VERSION 5.5 ;
NAMESCASESENSITIVE ON ;
BUSBITCHARS "[]" ;
DIVIDERCHAR "/" ;

PROPERTYDEFINITIONS
  LAYER routingPitch REAL ;
END PROPERTYDEFINITIONS

UNITS
  DATABASE MICRONS 1000 ;
END UNITS
MANUFACTURINGGRID 0.01 ;
LAYER POLY1
  TYPE MASTERSLICE ;
END POLY1

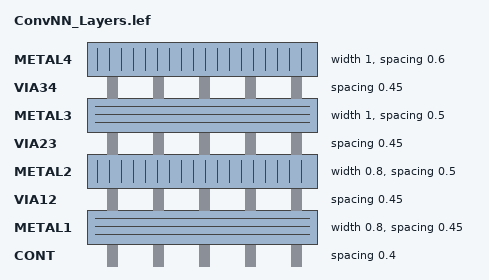
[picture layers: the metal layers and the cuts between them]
LAYER CONT
  TYPE CUT ;
  SPACING 0.4 ;
END CONT

LAYER METAL1
  TYPE ROUTING ;
  DIRECTION HORIZONTAL ;
  PITCH 0 ;
  WIDTH 0.8 ;
  SPACING 0.45 ;
  PROPERTY routingPitch 1.25 ;
END METAL1

LAYER VIA12
  TYPE CUT ;
  SPACING 0.45 ;
END VIA12

LAYER METAL2
  TYPE ROUTING ;
  DIRECTION VERTICAL ;
  PITCH 0 ;
  WIDTH 0.8 ;
  SPACING 0.5 ;
  PROPERTY routingPitch 1.4 ;
END METAL2

LAYER VIA23
  TYPE CUT ;
  SPACING 0.45 ;
END VIA23

LAYER METAL3
  TYPE ROUTING ;
  DIRECTION HORIZONTAL ;
  PITCH 0 ;
  WIDTH 1.0 ;
  SPACING 0.5 ;
  PROPERTY routingPitch 1.25 ;
END METAL3

LAYER VIA34
  TYPE CUT ;
  SPACING 0.45 ;
END VIA34

LAYER METAL4
  TYPE ROUTING ;
  DIRECTION VERTICAL ;
  PITCH 0 ;
  WIDTH 1.0 ;
  SPACING 0.6 ;
  PROPERTY routingPitch 1.4 ;
END METAL4

LAYER OVERLAP
  TYPE OVERLAP ;
END OVERLAP

VIARULE M4_M3 GENERATE
  LAYER METAL3 ;
    ENCLOSURE 0.2 0.2 ;
  LAYER METAL4 ;
    ENCLOSURE 0.15 0.15 ;
  LAYER VIA34 ;
    RECT -0.25 -0.25 0.25 0.25 ;
    SPACING 1 BY 1 ;
END M4_M3

VIARULE M3_M2 GENERATE
  LAYER METAL2 ;
    ENCLOSURE 0.2 0.2 ;
  LAYER METAL3 ;
    ENCLOSURE 0.15 0.15 ;
  LAYER VIA23 ;
    RECT -0.25 -0.25 0.25 0.25 ;
    SPACING 1 BY 1 ;
END M3_M2

VIARULE M2_M1 GENERATE
  LAYER METAL1 ;
    ENCLOSURE 0.2 0.2 ;
  LAYER METAL2 ;
    ENCLOSURE 0.15 0.15 ;
  LAYER VIA12 ;
    RECT -0.25 -0.25 0.25 0.25 ;
    SPACING 1 BY 1 ;
END M2_M1

VIARULE M1_POLY1 GENERATE
  LAYER POLY1 ;
    ENCLOSURE 0.2 0.2 ;
  LAYER METAL1 ;
    ENCLOSURE 0.15 0.15 ;
  LAYER CONT ;
    RECT -0.2 -0.2 0.2 0.2 ;
    SPACING 1 BY 1 ;
END M1_POLY1

VIA M1_POLY1
  LAYER CONT ;
    RECT -0.2 -0.2 0.2 0.2 ;
  LAYER POLY1 ;
    RECT -0.4 -0.4 0.4 0.4 ;
  LAYER METAL1 ;
    RECT -0.35 -0.35 0.35 0.35 ;
END M1_POLY1

VIA M2_M1
  LAYER VIA12 ;
    RECT -0.25 -0.25 0.25 0.25 ;
  LAYER METAL2 ;
    RECT -0.4 -0.4 0.4 0.4 ;
  LAYER METAL1 ;
    RECT -0.45 -0.45 0.45 0.45 ;
END M2_M1

VIA M3_M2
  LAYER VIA23 ;
    RECT -0.25 -0.25 0.25 0.25 ;
  LAYER METAL3 ;
    RECT -0.4 -0.4 0.4 0.4 ;
  LAYER METAL2 ;
    RECT -0.45 -0.45 0.45 0.45 ;
END M3_M2

VIA M4_M3
  LAYER VIA34 ;
    RECT -0.25 -0.25 0.25 0.25 ;
  LAYER METAL4 ;
    RECT -0.4 -0.4 0.4 0.4 ;
  LAYER METAL3 ;
    RECT -0.45 -0.45 0.45 0.45 ;
END M4_M3


MACRO TSMC350nm_VinjDecode2to4_vtile_spacing
END TSMC350nm_VinjDecode2to4_vtile_spacing

MACRO TSMC350nm_VinjDecode2to4_vtile_bridge_spacing
END TSMC350nm_VinjDecode2to4_vtile_bridge_spacing

MACRO TSMC350nm_VinjDecode2to4_vtile_D_bridge
END TSMC350nm_VinjDecode2to4_vtile_D_bridge

MACRO TSMC350nm_VinjDecode2to4_vtile
  PIN Vinj
    DIRECTION INOUT ;
    USE SIGNAL ;
    PORT
      LAYER METAL1 ;
        RECT 7.78 11.04 9.06 11.45 ;
    END
  END Vinj
  PIN OUT<0>
    DIRECTION INOUT ;
    USE SIGNAL ;
    PORT
      LAYER METAL1 ;
        RECT 19.66 18.91 20.11 19.59 ;
    END
  END OUT<0>
  PIN OUT<1>
    DIRECTION INOUT ;
    USE SIGNAL ;
    PORT
      LAYER METAL1 ;
        RECT 19.66 13.41 20.12 14.1 ;
    END
  END OUT<1>
  PIN OUT<2>
    DIRECTION INOUT ;
    USE SIGNAL ;
    PORT
      LAYER METAL1 ;
        RECT 19.66 7.92 20.11 8.59 ;
    END
  END OUT<2>
  PIN OUT<3>
    DIRECTION INOUT ;
    USE SIGNAL ;
    PORT
      LAYER METAL1 ;
        RECT 19.66 2.41 20.11 3.09 ;
    END
  END OUT<3>
  PIN ENABLE
    DIRECTION INOUT ;
    USE SIGNAL ;
    PORT
      LAYER METAL1 ;
        RECT 0.01 3.48 0.71 4.21 ;
    END
  END ENABLE
  PIN GND
    DIRECTION INOUT ;
    USE SIGNAL ;
    PORT
      LAYER METAL1 ;
        RECT 19.52 5.0 20.12 5.99 ;
    END
  END GND
  PIN VINJ
    DIRECTION INOUT ;
    USE SIGNAL ;
    PORT
      LAYER METAL1 ;
        RECT 19.15 21.56 20.05 21.96 ;
    END
  END VINJ
  PIN IN<1>
    DIRECTION INOUT ;
    USE SIGNAL ;
    PORT
      LAYER METAL2 ;
        RECT 6.56 20.89 7.5 22.0 ;
    END
  END IN<1>
  PIN IN<0>
    DIRECTION INOUT ;
    USE SIGNAL ;
    PORT
      LAYER METAL2 ;
        RECT 3.9 20.96 4.5 22.0 ;
    END
  END IN<0>
END TSMC350nm_VinjDecode2to4_vtile

MACRO TSMC350nm_VinjDecode2to4_vtile_C_bridge
END TSMC350nm_VinjDecode2to4_vtile_C_bridge

MACRO TSMC350nm_VinjDecode2to4_vtile_B_bridge
END TSMC350nm_VinjDecode2to4_vtile_B_bridge

MACRO TSMC350nm_VinjDecode2to4_vtile_A_bridge
END TSMC350nm_VinjDecode2to4_vtile_A_bridge

MACRO TSMC350nm_drainSelect_progrundrains
  PIN prog_drain<3>
    DIRECTION INOUT ;
    USE SIGNAL ;
    PORT
      LAYER METAL1 ;
        RECT 30.93 0.93 31.86 1.43 ;
    END
  END prog_drain<3>
  PIN prog_drain<2>
    DIRECTION INOUT ;
    USE SIGNAL ;
    PORT
      LAYER METAL1 ;
        RECT 30.97 9.62 31.86 10.12 ;
    END
  END prog_drain<2>
  PIN prog_drain<1>
    DIRECTION INOUT ;
    USE SIGNAL ;
    PORT
      LAYER METAL1 ;
        RECT 31.0 13.97 31.86 14.47 ;
    END
  END prog_drain<1>
  PIN run_drain<3>
    DIRECTION INOUT ;
    USE SIGNAL ;
    PORT
      LAYER METAL1 ;
        RECT 31.01 2.45 31.86 2.95 ;
    END
  END run_drain<3>
  PIN run_drain<2>
    DIRECTION INOUT ;
    USE SIGNAL ;
    PORT
      LAYER METAL1 ;
        RECT 30.94 5.31 31.86 5.81 ;
    END
  END run_drain<2>
  PIN prog_drain<0>
    DIRECTION INOUT ;
    USE SIGNAL ;
    PORT
      LAYER METAL1 ;
        RECT 31.12 20.75 31.86 21.25 ;
    END
  END prog_drain<0>
  PIN GND
    DIRECTION INOUT ;
    USE SIGNAL ;
    PORT
      LAYER METAL2 ;
        RECT 4.19 21.33 4.99 22.0 ;
    END
  END GND
  PIN VINJ
    DIRECTION INOUT ;
    USE SIGNAL ;
    PORT
      LAYER METAL1 ;
        RECT 1.4 21.5 2.8 22.0 ;
    END
  END VINJ
  PIN run_drain<0>
    DIRECTION INOUT ;
    USE SIGNAL ;
    PORT
      LAYER METAL1 ;
        RECT 31.01 19.56 31.86 20.06 ;
    END
  END run_drain<0>
  PIN run_drain<1>
    DIRECTION INOUT ;
    USE SIGNAL ;
    PORT
      LAYER METAL1 ;
        RECT 31.04 16.75 31.86 17.24 ;
    END
  END run_drain<1>
  PIN SELECT<3>
    DIRECTION INOUT ;
    USE SIGNAL ;
    PORT
      LAYER METAL1 ;
        RECT 0.0 2.54 0.67 2.97 ;
    END
  END SELECT<3>
  PIN SELET<2>
    DIRECTION INOUT ;
    USE SIGNAL ;
    PORT
      LAYER METAL1 ;
        RECT 0.0 8.03 0.67 8.46 ;
    END
  END SELET<2>
  PIN SELECT<1>
    DIRECTION INOUT ;
    USE SIGNAL ;
    PORT
      LAYER METAL1 ;
        RECT 0.0 13.54 0.67 13.97 ;
    END
  END SELECT<1>
  PIN SELECT<0>
    DIRECTION INOUT ;
    USE SIGNAL ;
    PORT
      LAYER METAL1 ;
        RECT 0.0 18.9 0.67 19.6 ;
    END
  END SELECT<0>
  PIN VINJ_b
    DIRECTION INOUT ;
    USE SIGNAL ;
    PORT
      LAYER METAL2 ;
        RECT 21.94 0.0 23.29 0.58 ;
    END
  END VINJ_b
  PIN GND_b
    DIRECTION INOUT ;
    USE SIGNAL ;
    PORT
      LAYER METAL2 ;
        RECT 17.16 0.0 18.16 0.58 ;
    END
  END GND_b
  PIN run_drainrail
    DIRECTION INOUT ;
    USE SIGNAL ;
    PORT
      LAYER METAL2 ;
        RECT 27.01 21.19 27.71 22.0 ;
    END
  END run_drainrail
  PIN prog_drainrail
    DIRECTION INOUT ;
    USE SIGNAL ;
    PORT
      LAYER METAL2 ;
        RECT 7.36 21.34 8.16 22.0 ;
    END
  END prog_drainrail
END TSMC350nm_drainSelect_progrundrains

MACRO TSMC350nm_4TGate_ST_draincutoff
  PIN In<0>
    DIRECTION INOUT ;
    USE SIGNAL ;
    PORT
      LAYER METAL1 ;
        RECT 9.96 17.5 10.6 18.45 ;
    END
  END In<0>
  PIN In<1>
    DIRECTION INOUT ;
    USE SIGNAL ;
    PORT
      LAYER METAL1 ;
        RECT 9.91 14.7 10.6 15.93 ;
    END
  END In<1>
  PIN In<2>
    DIRECTION INOUT ;
    USE SIGNAL ;
    PORT
      LAYER METAL1 ;
        RECT 10.01 6.9 10.6 7.8 ;
    END
  END In<2>
  PIN In<3>
    DIRECTION INOUT ;
    USE SIGNAL ;
    PORT
      LAYER METAL1 ;
        RECT 10.02 3.5 10.6 4.3 ;
    END
  END In<3>
  PIN A<0>
    DIRECTION INOUT ;
    USE SIGNAL ;
    PORT
      LAYER METAL1 ;
        RECT 0.0 19.56 1.4 20.06 ;
    END
  END A<0>
  PIN A<1>
    DIRECTION INOUT ;
    USE SIGNAL ;
    PORT
      LAYER METAL1 ;
        RECT 0.0 16.75 1.4 17.25 ;
    END
  END A<1>
  PIN A<2>
    DIRECTION INOUT ;
    USE SIGNAL ;
    PORT
      LAYER METAL1 ;
        RECT 0.0 5.3 1.4 5.8 ;
    END
  END A<2>
  PIN A<3>
    DIRECTION INOUT ;
    USE SIGNAL ;
    PORT
      LAYER METAL1 ;
        RECT 0.0 2.45 1.4 2.95 ;
    END
  END A<3>
  PIN P<0>
    DIRECTION INOUT ;
    USE SIGNAL ;
    PORT
      LAYER METAL1 ;
        RECT 0.0 20.75 1.4 21.25 ;
    END
  END P<0>
  PIN P<1>
    DIRECTION INOUT ;
    USE SIGNAL ;
    PORT
      LAYER METAL1 ;
        RECT 0.0 13.97 1.4 14.47 ;
    END
  END P<1>
  PIN P<2>
    DIRECTION INOUT ;
    USE SIGNAL ;
    PORT
      LAYER METAL1 ;
        RECT 0.0 9.62 1.4 10.12 ;
    END
  END P<2>
  PIN P<3>
    DIRECTION INOUT ;
    USE SIGNAL ;
    PORT
      LAYER METAL1 ;
        RECT 0.0 0.93 1.4 1.43 ;
    END
  END P<3>
  PIN PR<0>
    DIRECTION INOUT ;
    USE SIGNAL ;
    PORT
      LAYER METAL1 ;
        RECT 10.0 20.3 10.6 21.25 ;
    END
  END PR<0>
  PIN PR<1>
    DIRECTION INOUT ;
    USE SIGNAL ;
    PORT
      LAYER METAL1 ;
        RECT 10.13 11.9 10.6 12.8 ;
    END
  END PR<1>
  PIN PR<2>
    DIRECTION INOUT ;
    USE SIGNAL ;
    PORT
      LAYER METAL1 ;
        RECT 10.0 9.4 10.6 10.3 ;
    END
  END PR<2>
  PIN PR<3>
    DIRECTION INOUT ;
    USE SIGNAL ;
    PORT
      LAYER METAL1 ;
        RECT 10.0 0.7 10.6 1.6 ;
    END
  END PR<3>
  PIN VDD_b
    DIRECTION INOUT ;
    USE SIGNAL ;
    PORT
      LAYER METAL2 ;
        RECT 7.89 0.0 8.79 0.54 ;
    END
  END VDD_b
  PIN RUN
    DIRECTION INOUT ;
    USE SIGNAL ;
    PORT
      LAYER METAL2 ;
        RECT 5.9 21.13 6.5 22.0 ;
    END
  END RUN
  PIN VDD
    DIRECTION INOUT ;
    USE SIGNAL ;
    PORT
      LAYER METAL2 ;
        RECT 7.89 21.3 8.79 22.0 ;
    END
  END VDD
  PIN GND
    DIRECTION INOUT ;
    USE SIGNAL ;
    PORT
      LAYER METAL2 ;
        RECT 3.35 21.3 4.25 22.0 ;
    END
  END GND
  PIN GND_b
    DIRECTION INOUT ;
    USE SIGNAL ;
    PORT
      LAYER METAL2 ;
        RECT 3.35 0.0 4.25 0.73 ;
    END
  END GND_b
  PIN RUN_b
    DIRECTION INOUT ;
    USE SIGNAL ;
    PORT
      LAYER METAL2 ;
        RECT 5.9 0.0 6.5 0.71 ;
    END
  END RUN_b
END TSMC350nm_4TGate_ST_draincutoff

MACRO TSMC350nm_IndirectSwitches
  PIN GND_B<1>
    DIRECTION INOUT ;
    USE SIGNAL ;
    PORT
      LAYER METAL2 ;
        RECT 15.41 0.0 16.01 0.85 ;
    END
  END GND_B<1>
  PIN GND_B<0>
    DIRECTION INOUT ;
    USE SIGNAL ;
    PORT
      LAYER METAL2 ;
        RECT 11.2 0.0 11.8 0.85 ;
    END
  END GND_B<0>
  PIN GND
    DIRECTION INOUT ;
    USE SIGNAL ;
    PORT
      LAYER METAL2 ;
        RECT 11.2 3.21 11.8 3.6 ;
    END
  END GND
  PIN GND_T
    DIRECTION INOUT ;
    USE SIGNAL ;
    PORT
      LAYER METAL2 ;
        RECT 15.4 21.0 16.2 22.0 ;
    END
  END GND_T
  PIN VINJ_T
    DIRECTION INOUT ;
    USE SIGNAL ;
    PORT
      LAYER METAL2 ;
        RECT 6.3 21.04 7.32 22.0 ;
    END
  END VINJ_T
  PIN VDD<1>
    DIRECTION INOUT ;
    USE SIGNAL ;
    PORT
      LAYER METAL2 ;
        RECT 24.5 0.0 25.1 0.75 ;
    END
  END VDD<1>
  PIN VTUN
    DIRECTION INOUT ;
    USE SIGNAL ;
    PORT
      LAYER METAL2 ;
        RECT 13.3 0.0 13.9 0.82 ;
    END
  END VTUN
  PIN VINJ
    DIRECTION INOUT ;
    USE SIGNAL ;
    PORT
      LAYER METAL2 ;
        RECT 4.2 0.0 4.8 1.0 ;
    END
  END VINJ
  PIN VDD<0>
    DIRECTION INOUT ;
    USE SIGNAL ;
    PORT
      LAYER METAL2 ;
        RECT 2.1 0.0 2.7 1.09 ;
    END
  END VDD<0>
  PIN Vg<0>
    DIRECTION INOUT ;
    USE SIGNAL ;
    PORT
      LAYER METAL2 ;
        RECT 8.4 0.005 9.0 0.825 ;
    END
  END Vg<0>
  PIN CTRL_B<0>
    DIRECTION INOUT ;
    USE SIGNAL ;
    PORT
      LAYER METAL2 ;
        RECT 6.3 0.01 6.9 0.76 ;
    END
  END CTRL_B<0>
  PIN CTRL_B<1>
    DIRECTION INOUT ;
    USE SIGNAL ;
    PORT
      LAYER METAL2 ;
        RECT 20.3 0.01 20.9 0.75 ;
    END
  END CTRL_B<1>
  PIN Vg<1>
    DIRECTION INOUT ;
    USE SIGNAL ;
    PORT
      LAYER METAL2 ;
        RECT 18.2 0.0 18.8 0.76 ;
    END
  END Vg<1>
  PIN decode<0>
    DIRECTION INOUT ;
    USE SIGNAL ;
    PORT
      LAYER METAL2 ;
        RECT 3.46 21.16 4.8 22.0 ;
    END
  END decode<0>
  PIN RUN_IN<1>
    DIRECTION INOUT ;
    USE SIGNAL ;
    PORT
      LAYER METAL2 ;
        RECT 17.5 21.01 18.1 22.0 ;
    END
  END RUN_IN<1>
  PIN RUN_IN<0>
    DIRECTION INOUT ;
    USE SIGNAL ;
    PORT
      LAYER METAL2 ;
        RECT 10.5 20.9 11.1 22.0 ;
    END
  END RUN_IN<0>
  PIN VPWR<1>
    DIRECTION INOUT ;
    USE SIGNAL ;
    PORT
      LAYER METAL2 ;
        RECT 21.7 21.08 22.3 22.0 ;
    END
  END VPWR<1>
  PIN decode<1>
    DIRECTION INOUT ;
    USE SIGNAL ;
    PORT
      LAYER METAL2 ;
        RECT 23.8 21.09 25.0 22.0 ;
    END
  END decode<1>
  PIN VPWR<0>
    DIRECTION INOUT ;
    USE SIGNAL ;
    PORT
      LAYER METAL2 ;
        RECT 1.71 21.21 2.43 22.0 ;
    END
  END VPWR<0>
  PIN VTUN_T
    DIRECTION INOUT ;
    USE SIGNAL ;
    PORT
      LAYER METAL2 ;
        RECT 12.6 21.12 13.7 22.0 ;
    END
  END VTUN_T
  PIN vtun_r
    DIRECTION INOUT ;
    USE SIGNAL ;
    PORT
      LAYER METAL1 ;
        RECT 26.17 0.9 27.46 2.17 ;
    END
  END vtun_r
  PIN vgsel_r
    DIRECTION INOUT ;
    USE SIGNAL ;
    PORT
      LAYER METAL1 ;
        RECT 26.52 3.15 27.46 4.45 ;
    END
  END vgsel_r
  PIN prog_r
    DIRECTION INOUT ;
    USE SIGNAL ;
    PORT
      LAYER METAL1 ;
        RECT 26.59 9.15 27.46 10.55 ;
    END
  END prog_r
  PIN run_r
    DIRECTION INOUT ;
    USE SIGNAL ;
    PORT
      LAYER METAL1 ;
        RECT 26.28 6.05 27.46 7.29 ;
    END
  END run_r
  PIN RUN
    DIRECTION INOUT ;
    USE SIGNAL ;
    PORT
      LAYER METAL1 ;
        RECT 0.0 6.05 0.91 7.29 ;
    END
  END RUN
  PIN PROG
    DIRECTION INOUT ;
    USE SIGNAL ;
    PORT
      LAYER METAL1 ;
        RECT 0.0 9.15 0.87 10.55 ;
    END
  END PROG
  PIN Vgsel
    DIRECTION INOUT ;
    USE SIGNAL ;
    PORT
      LAYER METAL1 ;
        RECT 0.0 3.72 0.91 4.45 ;
    END
  END Vgsel
  PIN vtun_l
    DIRECTION INOUT ;
    USE SIGNAL ;
    PORT
      LAYER METAL1 ;
        RECT 0.0 0.9 1.31 1.88 ;
    END
  END vtun_l
END TSMC350nm_IndirectSwitches

MACRO TSMC350nm_VinjDecode2to4_htile
  PIN IN<1>
    DIRECTION INOUT ;
    USE SIGNAL ;
    PORT
      LAYER METAL1 ;
        RECT 0.0 11.85 0.9 12.74 ;
    END
  END IN<1>
  PIN IN<0>
    DIRECTION INOUT ;
    USE SIGNAL ;
    PORT
      LAYER METAL1 ;
        RECT 0.0 10.13 0.87 11.1 ;
    END
  END IN<0>
  PIN VINJ
    DIRECTION INOUT ;
    USE SIGNAL ;
    PORT
      LAYER METAL1 ;
        RECT 0.0 1.99 0.5 2.49 ;
    END
  END VINJ
  PIN GND
    DIRECTION INOUT ;
    USE SIGNAL ;
    PORT
      LAYER METAL1 ;
        RECT 0.0 6.99 0.51 7.49 ;
    END
  END GND
  PIN GND_b<1>
    DIRECTION INOUT ;
    USE SIGNAL ;
    PORT
      LAYER METAL2 ;
        RECT 40.32 0.0 40.92 1.79 ;
    END
  END GND_b<1>
  PIN VINJ_b<1>
    DIRECTION INOUT ;
    USE SIGNAL ;
    PORT
      LAYER METAL2 ;
        RECT 22.1 0.0 22.7 1.44 ;
    END
  END VINJ_b<1>
  PIN GND_b<0>
    DIRECTION INOUT ;
    USE SIGNAL ;
    PORT
      LAYER METAL2 ;
        RECT 18.85 0.0 19.45 1.41 ;
    END
  END GND_b<0>
  PIN VINJ_b<0>
    DIRECTION INOUT ;
    USE SIGNAL ;
    PORT
      LAYER METAL2 ;
        RECT 1.07 0.0 1.67 1.25 ;
    END
  END VINJ_b<0>
  PIN VINJV
    DIRECTION INOUT ;
    USE SIGNAL ;
    PORT
      LAYER METAL2 ;
        RECT 23.7 21.26 24.31 22.0 ;
    END
  END VINJV
  PIN GNDV
    DIRECTION INOUT ;
    USE SIGNAL ;
    PORT
      LAYER METAL2 ;
        RECT 25.84 21.28 26.44 22.0 ;
    END
  END GNDV
  PIN RUN_OUT<3>
    DIRECTION INOUT ;
    USE SIGNAL ;
    PORT
      LAYER METAL2 ;
        RECT 34.39 0.0 35.19 0.86 ;
    END
  END RUN_OUT<3>
  PIN RUN_OUT<2>
    DIRECTION INOUT ;
    USE SIGNAL ;
    PORT
      LAYER METAL2 ;
        RECT 28.77 0.0 29.57 0.86 ;
    END
  END RUN_OUT<2>
  PIN RUN_OUT<1>
    DIRECTION INOUT ;
    USE SIGNAL ;
    PORT
      LAYER METAL2 ;
        RECT 13.5 0.0 14.1 0.86 ;
    END
  END RUN_OUT<1>
  PIN RUN_OUT<0>
    DIRECTION INOUT ;
    USE SIGNAL ;
    PORT
      LAYER METAL2 ;
        RECT 7.34 0.0 8.14 0.86 ;
    END
  END RUN_OUT<0>
  PIN ENABLE
    DIRECTION INOUT ;
    USE SIGNAL ;
    PORT
      LAYER METAL2 ;
        RECT 6.29 21.66 6.89 22.0 ;
    END
  END ENABLE
  PIN OUT<2>
    DIRECTION INOUT ;
    USE SIGNAL ;
    PORT
      LAYER METAL2 ;
        RECT 25.28 0.0 25.87 0.87 ;
    END
  END OUT<2>
  PIN OUT<3>
    DIRECTION INOUT ;
    USE SIGNAL ;
    PORT
      LAYER METAL2 ;
        RECT 37.14 0.0 37.73 0.83 ;
    END
  END OUT<3>
  PIN OUT<0>
    DIRECTION INOUT ;
    USE SIGNAL ;
    PORT
      LAYER METAL2 ;
        RECT 4.27 0.0 4.87 0.86 ;
    END
  END OUT<0>
  PIN OUT<1>
    DIRECTION INOUT ;
    USE SIGNAL ;
    PORT
      LAYER METAL2 ;
        RECT 16.14 0.0 16.72 0.85 ;
    END
  END OUT<1>
  PIN VGRUN<0>
    DIRECTION INOUT ;
    USE SIGNAL ;
    PORT
      LAYER METAL2 ;
        RECT 9.1 21.59 9.7 22.0 ;
    END
  END VGRUN<0>
  PIN VGRUN<1>
    DIRECTION INOUT ;
    USE SIGNAL ;
    PORT
      LAYER METAL2 ;
        RECT 11.2 21.6 11.8 22.0 ;
    END
  END VGRUN<1>
  PIN VGRUN<2>
    DIRECTION INOUT ;
    USE SIGNAL ;
    PORT
      LAYER METAL2 ;
        RECT 28.7 21.71 29.3 22.0 ;
    END
  END VGRUN<2>
  PIN VGRUN<3>
    DIRECTION INOUT ;
    USE SIGNAL ;
    PORT
      LAYER METAL2 ;
        RECT 33.6 21.54 34.2 22.0 ;
    END
  END VGRUN<3>
END TSMC350nm_VinjDecode2to4_htile

MACRO TSMC350nm_VinjDecode2to4_htile_A_bridge
  PIN VGRUN<3>
    DIRECTION INOUT ;
    USE SIGNAL ;
    PORT
      LAYER METAL2 ;
        RECT 34.5 9.46 35.1 10.0 ;
    END
  END VGRUN<3>
  PIN VGRUN<2>
    DIRECTION INOUT ;
    USE SIGNAL ;
    PORT
      LAYER METAL2 ;
        RECT 26.6 9.56 27.2 10.0 ;
    END
  END VGRUN<2>
  PIN VGRUN<1>
    DIRECTION INOUT ;
    USE SIGNAL ;
    PORT
      LAYER METAL2 ;
        RECT 13.5 9.46 14.1 10.0 ;
    END
  END VGRUN<1>
  PIN VGRUN<0>
    DIRECTION INOUT ;
    USE SIGNAL ;
    PORT
      LAYER METAL2 ;
        RECT 5.6 9.52 6.2 10.0 ;
    END
  END VGRUN<0>
END TSMC350nm_VinjDecode2to4_htile_A_bridge

MACRO TSMC350nm_VinjDecode2to4_htile_B_bridge
  PIN VGRUN<0>
    DIRECTION INOUT ;
    USE SIGNAL ;
    PORT
      LAYER METAL2 ;
        RECT 9.1 9.52 9.7 10.0 ;
    END
  END VGRUN<0>
  PIN VGRUN<1>
    DIRECTION INOUT ;
    USE SIGNAL ;
    PORT
      LAYER METAL2 ;
        RECT 11.2 9.52 11.8 10.0 ;
    END
  END VGRUN<1>
  PIN VGRUN<2>
    DIRECTION INOUT ;
    USE SIGNAL ;
    PORT
      LAYER METAL2 ;
        RECT 28.7 9.5 29.3 10.0 ;
    END
  END VGRUN<2>
  PIN VGRUN<3>
    DIRECTION INOUT ;
    USE SIGNAL ;
    PORT
      LAYER METAL2 ;
        RECT 33.6 9.51 34.2 10.0 ;
    END
  END VGRUN<3>
END TSMC350nm_VinjDecode2to4_htile_B_bridge

MACRO TSMC350nm_VinjDecode2to4_htile_C_bridge
  PIN VGRUN<0>
    DIRECTION INOUT ;
    USE SIGNAL ;
    PORT
      LAYER METAL2 ;
        RECT 9.1 9.54 9.7 10.0 ;
    END
  END VGRUN<0>
  PIN VGRUN<1>
    DIRECTION INOUT ;
    USE SIGNAL ;
    PORT
      LAYER METAL2 ;
        RECT 11.2 9.57 11.8 10.0 ;
    END
  END VGRUN<1>
  PIN VGRUN<2>
    DIRECTION INOUT ;
    USE SIGNAL ;
    PORT
      LAYER METAL2 ;
        RECT 28.7 9.59 29.3 10.0 ;
    END
  END VGRUN<2>
  PIN VGRUN<3>
    DIRECTION INOUT ;
    USE SIGNAL ;
    PORT
      LAYER METAL2 ;
        RECT 33.6 9.57 34.2 10.0 ;
    END
  END VGRUN<3>
END TSMC350nm_VinjDecode2to4_htile_C_bridge

MACRO TSMC350nm_VinjDecode2to4_htile_spacing
  PIN VGRUN<0>
    DIRECTION INOUT ;
    USE SIGNAL ;
    PORT
      LAYER METAL2 ;
        RECT 9.1 21.59 9.7 22.0 ;
    END
  END VGRUN<0>
  PIN VGRUN<1>
    DIRECTION INOUT ;
    USE SIGNAL ;
    PORT
      LAYER METAL2 ;
        RECT 11.2 21.52 11.8 22.0 ;
    END
  END VGRUN<1>
  PIN VGRUN<2>
    DIRECTION INOUT ;
    USE SIGNAL ;
    PORT
      LAYER METAL2 ;
        RECT 28.7 21.54 29.3 22.0 ;
    END
  END VGRUN<2>
  PIN VGRUN<3>
    DIRECTION INOUT ;
    USE SIGNAL ;
    PORT
      LAYER METAL2 ;
        RECT 33.6 21.55 34.2 22.0 ;
    END
  END VGRUN<3>
END TSMC350nm_VinjDecode2to4_htile_spacing

MACRO Tgate_swc_fr_Kernel_Vert
  PIN Vimg
    DIRECTION INOUT ;
    USE SIGNAL ;
    PORT
      LAYER METAL1 ;
        RECT 0.0 17.02 0.39 17.72 ;
    END
  END Vimg
  PIN AVDD
    DIRECTION INOUT ;
    USE SIGNAL ;
    PORT
      LAYER METAL1 ;
        RECT 0.0 14.02 0.39 15.02 ;
    END
  END AVDD
  PIN DVDD
    DIRECTION INOUT ;
    USE SIGNAL ;
    PORT
      LAYER METAL1 ;
        RECT 0.0 9.47 0.39 10.47 ;
    END
  END DVDD
  PIN GND
    DIRECTION INOUT ;
    USE SIGNAL ;
    PORT
      LAYER METAL2 ;
        RECT 4.39 21.77 5.19 22.0 ;
    END
  END GND
  PIN Q_bot
    DIRECTION INOUT ;
    USE SIGNAL ;
    PORT
      LAYER METAL2 ;
        RECT 6.57 0.0 7.35 0.35 ;
    END
  END Q_bot
  PIN Vg_R
    DIRECTION INOUT ;
    USE SIGNAL ;
    PORT
      LAYER METAL2 ;
        RECT 1.25 0.0 2.05 0.35 ;
    END
  END Vg_R
  PIN Q
    DIRECTION INOUT ;
    USE SIGNAL ;
    PORT
      LAYER METAL2 ;
        RECT 8.6 21.77 9.2 22.0 ;
    END
  END Q
END Tgate_swc_fr_Kernel_Vert

MACRO AvgPool_TopDig
  PIN intg_nxt_rw
    DIRECTION INOUT ;
    USE SIGNAL ;
    PORT
      LAYER METAL2 ;
        RECT 123.32 0.0 124.72 0.68 ;
    END
  END intg_nxt_rw
  PIN AvgPool_col_ctrl<1>
    DIRECTION INOUT ;
    USE SIGNAL ;
    PORT
      LAYER METAL2 ;
        RECT 98.63 0.0 100.03 0.68 ;
    END
  END AvgPool_col_ctrl<1>
  PIN SR_int_0_Q<2>
    DIRECTION INOUT ;
    USE SIGNAL ;
    PORT
      LAYER METAL2 ;
        RECT 73.89 0.0 75.29 0.68 ;
    END
  END SR_int_0_Q<2>
  PIN SR_int_0_Q<4>
    DIRECTION INOUT ;
    USE SIGNAL ;
    PORT
      LAYER METAL2 ;
        RECT 67.9 0.0 69.3 0.68 ;
    END
  END SR_int_0_Q<4>
  PIN SR_int_0_Q<6>
    DIRECTION INOUT ;
    USE SIGNAL ;
    PORT
      LAYER METAL2 ;
        RECT 61.83 0.0 63.23 0.68 ;
    END
  END SR_int_0_Q<6>
  PIN AvgPool_col_ctrl<0>
    DIRECTION INOUT ;
    USE SIGNAL ;
    PORT
      LAYER METAL2 ;
        RECT 116.11 0.0 117.51 0.68 ;
    END
  END AvgPool_col_ctrl<0>
  PIN SR_int_0_Q<1>
    DIRECTION INOUT ;
    USE SIGNAL ;
    PORT
      LAYER METAL2 ;
        RECT 19.86 0.0 21.26 0.68 ;
    END
  END SR_int_0_Q<1>
  PIN SR_int_0_Q<3>
    DIRECTION INOUT ;
    USE SIGNAL ;
    PORT
      LAYER METAL2 ;
        RECT 25.91 0.0 27.31 0.68 ;
    END
  END SR_int_0_Q<3>
  PIN SR_int_0_Q<0>
    DIRECTION INOUT ;
    USE SIGNAL ;
    PORT
      LAYER METAL2 ;
        RECT 31.89 0.0 33.29 0.68 ;
    END
  END SR_int_0_Q<0>
  PIN SR_int_0_Q<7>
    DIRECTION INOUT ;
    USE SIGNAL ;
    PORT
      LAYER METAL2 ;
        RECT 37.86 0.0 39.26 0.68 ;
    END
  END SR_int_0_Q<7>
  PIN SR_int_0_Q<5>
    DIRECTION INOUT ;
    USE SIGNAL ;
    PORT
      LAYER METAL2 ;
        RECT 49.86 0.0 51.26 0.68 ;
    END
  END SR_int_0_Q<5>
  PIN int_rst<0>
    DIRECTION INOUT ;
    USE SIGNAL ;
    PORT
      LAYER METAL1 ;
        RECT 132.77 29.44 133.45 30.84 ;
    END
  END int_rst<0>
  PIN Global_rst_b
    DIRECTION INOUT ;
    USE SIGNAL ;
    PORT
      LAYER METAL1 ;
        RECT 132.77 47.29 133.45 48.69 ;
    END
  END Global_rst_b
  PIN int_rst<1>
    DIRECTION INOUT ;
    USE SIGNAL ;
    PORT
      LAYER METAL1 ;
        RECT 132.77 56.93 133.45 58.33 ;
    END
  END int_rst<1>
  PIN Relu_en_b<0>
    DIRECTION INOUT ;
    USE SIGNAL ;
    PORT
      LAYER METAL1 ;
        RECT 132.77 40.37 133.45 41.77 ;
    END
  END Relu_en_b<0>
  PIN Relu_en_b<1>
    DIRECTION INOUT ;
    USE SIGNAL ;
    PORT
      LAYER METAL1 ;
        RECT 132.77 22.47 133.45 23.87 ;
    END
  END Relu_en_b<1>
  PIN GND
    DIRECTION INOUT ;
    USE SIGNAL ;
    PORT
      LAYER METAL1 ;
        RECT 132.77 6.16 133.45 7.99 ;
    END
  END GND
  PIN DVDD
    DIRECTION INOUT ;
    USE SIGNAL ;
    PORT
      LAYER METAL1 ;
        RECT 132.77 16.35 133.45 18.18 ;
    END
  END DVDD
  PIN SR_int_CLK
    DIRECTION INOUT ;
    USE SIGNAL ;
    PORT
      LAYER METAL1 ;
        RECT 0.0 26.72 0.68 28.12 ;
    END
  END SR_int_CLK
  PIN SR_int_CLKB
    DIRECTION INOUT ;
    USE SIGNAL ;
    PORT
      LAYER METAL1 ;
        RECT 0.0 31.64 0.68 33.04 ;
    END
  END SR_int_CLKB
  PIN SR_int_RST_B
    DIRECTION INOUT ;
    USE SIGNAL ;
    PORT
      LAYER METAL1 ;
        RECT 0.0 37.24 0.68 38.64 ;
    END
  END SR_int_RST_B
  PIN Final_rw
    DIRECTION INOUT ;
    USE SIGNAL ;
    PORT
      LAYER METAL1 ;
        RECT 0.0 40.94 0.68 42.34 ;
    END
  END Final_rw
  PIN SR_k_row_CLKB
    DIRECTION INOUT ;
    USE SIGNAL ;
    PORT
      LAYER METAL1 ;
        RECT 0.0 48.47 0.68 49.87 ;
    END
  END SR_k_row_CLKB
  PIN SR_k_row_RST_B
    DIRECTION INOUT ;
    USE SIGNAL ;
    PORT
      LAYER METAL1 ;
        RECT 0.0 51.32 0.68 52.72 ;
    END
  END SR_k_row_RST_B
  PIN SR_k_row_CLK
    DIRECTION INOUT ;
    USE SIGNAL ;
    PORT
      LAYER METAL1 ;
        RECT 0.0 55.55 0.68 56.95 ;
    END
  END SR_k_row_CLK
END AvgPool_TopDig

MACRO TSMC350nm_4TGate_ST_BMatrix
  PIN In<0>
    DIRECTION INOUT ;
    USE SIGNAL ;
    PORT
      LAYER METAL1 ;
        RECT 0.0 17.5 0.27 18.0 ;
    END
  END In<0>
  PIN In<1>
    DIRECTION INOUT ;
    USE SIGNAL ;
    PORT
      LAYER METAL1 ;
        RECT 0.0 14.7 0.38 15.2 ;
    END
  END In<1>
  PIN In<2>
    DIRECTION INOUT ;
    USE SIGNAL ;
    PORT
      LAYER METAL1 ;
        RECT 0.0 7.0 0.36 7.5 ;
    END
  END In<2>
  PIN In<3>
    DIRECTION INOUT ;
    USE SIGNAL ;
    PORT
      LAYER METAL1 ;
        RECT 0.0 3.5 0.3 4.0 ;
    END
  END In<3>
  PIN A<0>
    DIRECTION INOUT ;
    USE SIGNAL ;
    PORT
      LAYER METAL1 ;
        RECT 10.6 17.6 12.0 18.9 ;
    END
  END A<0>
  PIN A<1>
    DIRECTION INOUT ;
    USE SIGNAL ;
    PORT
      LAYER METAL1 ;
        RECT 10.6 14.9 12.0 16.2 ;
    END
  END A<1>
  PIN A<2>
    DIRECTION INOUT ;
    USE SIGNAL ;
    PORT
      LAYER METAL1 ;
        RECT 10.6 6.8 12.0 8.1 ;
    END
  END A<2>
  PIN A<3>
    DIRECTION INOUT ;
    USE SIGNAL ;
    PORT
      LAYER METAL1 ;
        RECT 10.6 4.1 12.0 5.4 ;
    END
  END A<3>
  PIN P<0>
    DIRECTION INOUT ;
    USE SIGNAL ;
    PORT
      LAYER METAL1 ;
        RECT 10.6 20.3 12.0 21.6 ;
    END
  END P<0>
  PIN P<1>
    DIRECTION INOUT ;
    USE SIGNAL ;
    PORT
      LAYER METAL1 ;
        RECT 10.6 12.2 12.0 13.5 ;
    END
  END P<1>
  PIN P<2>
    DIRECTION INOUT ;
    USE SIGNAL ;
    PORT
      LAYER METAL1 ;
        RECT 10.6 9.5 12.0 10.8 ;
    END
  END P<2>
  PIN P<3>
    DIRECTION INOUT ;
    USE SIGNAL ;
    PORT
      LAYER METAL1 ;
        RECT 10.6 1.4 12.0 2.7 ;
    END
  END P<3>
  PIN GND_b
    DIRECTION INOUT ;
    USE SIGNAL ;
    PORT
      LAYER METAL2 ;
        RECT 6.35 0.0 7.25 0.88 ;
    END
  END GND_b
  PIN Prog_b
    DIRECTION INOUT ;
    USE SIGNAL ;
    PORT
      LAYER METAL2 ;
        RECT 4.1 0.0 4.7 0.78 ;
    END
  END Prog_b
  PIN VDD_b
    DIRECTION INOUT ;
    USE SIGNAL ;
    PORT
      LAYER METAL2 ;
        RECT 1.81 0.0 2.71 0.71 ;
    END
  END VDD_b
  PIN Prog
    DIRECTION INOUT ;
    USE SIGNAL ;
    PORT
      LAYER METAL2 ;
        RECT 4.1 21.3 4.7 22.0 ;
    END
  END Prog
  PIN VDD
    DIRECTION INOUT ;
    USE SIGNAL ;
    PORT
      LAYER METAL2 ;
        RECT 1.81 21.3 2.71 22.0 ;
    END
  END VDD
  PIN GND
    DIRECTION INOUT ;
    USE SIGNAL ;
    PORT
      LAYER METAL2 ;
        RECT 6.35 21.3 7.25 22.0 ;
    END
  END GND
END TSMC350nm_4TGate_ST_BMatrix

MACRO TSMC350nm_VinjDecode2to4_htile_D_bridge
  PIN VGRUN<0>
    DIRECTION INOUT ;
    USE SIGNAL ;
    PORT
      LAYER METAL2 ;
        RECT 9.1 9.58 9.7 10.0 ;
    END
  END VGRUN<0>
  PIN VGRUN<1>
    DIRECTION INOUT ;
    USE SIGNAL ;
    PORT
      LAYER METAL2 ;
        RECT 11.2 9.55 11.8 10.0 ;
    END
  END VGRUN<1>
  PIN VGRUN<2>
    DIRECTION INOUT ;
    USE SIGNAL ;
    PORT
      LAYER METAL2 ;
        RECT 28.7 9.58 29.3 10.0 ;
    END
  END VGRUN<2>
  PIN VGRUN<3>
    DIRECTION INOUT ;
    USE SIGNAL ;
    PORT
      LAYER METAL2 ;
        RECT 33.6 9.57 34.2 10.0 ;
    END
  END VGRUN<3>
END TSMC350nm_VinjDecode2to4_htile_D_bridge

MACRO TSMC350nm_VinjDecode2to4_htile_bridge_spacing
  PIN VGRUN<0>
    DIRECTION INOUT ;
    USE SIGNAL ;
    PORT
      LAYER METAL2 ;
        RECT 9.1 9.52 9.7 9.99 ;
    END
  END VGRUN<0>
  PIN VGRUN<1>
    DIRECTION INOUT ;
    USE SIGNAL ;
    PORT
      LAYER METAL2 ;
        RECT 11.2 9.51 11.8 9.99 ;
    END
  END VGRUN<1>
  PIN VGRUN<2>
    DIRECTION INOUT ;
    USE SIGNAL ;
    PORT
      LAYER METAL2 ;
        RECT 28.7 9.41 29.3 9.99 ;
    END
  END VGRUN<2>
  PIN VGRUN<3>
    DIRECTION INOUT ;
    USE SIGNAL ;
    PORT
      LAYER METAL2 ;
        RECT 33.6 9.47 34.2 9.99 ;
    END
  END VGRUN<3>
END TSMC350nm_VinjDecode2to4_htile_bridge_spacing

MACRO Conv_TopDig
  PIN SR_int_0_Q<0>
    DIRECTION INOUT ;
    USE SIGNAL ;
    PORT
      LAYER METAL2 ;
        RECT 34.15 0.0 35.55 0.68 ;
    END
  END SR_int_0_Q<0>
  PIN SR_int_CLK
    DIRECTION INOUT ;
    USE SIGNAL ;
    PORT
      LAYER METAL2 ;
        RECT 20.27 0.0 21.67 0.68 ;
    END
  END SR_int_CLK
  PIN SR_int_CLKB
    DIRECTION INOUT ;
    USE SIGNAL ;
    PORT
      LAYER METAL2 ;
        RECT 23.72 0.0 25.12 0.68 ;
    END
  END SR_int_CLKB
  PIN SR_int_RST_B
    DIRECTION INOUT ;
    USE SIGNAL ;
    PORT
      LAYER METAL2 ;
        RECT 1.66 0.0 3.06 0.68 ;
    END
  END SR_int_RST_B
  PIN Final_rw
    DIRECTION INOUT ;
    USE SIGNAL ;
    PORT
      LAYER METAL2 ;
        RECT 15.0 43.32 16.4 44.0 ;
    END
  END Final_rw
  PIN SR_int_0_Q2
    DIRECTION INOUT ;
    USE SIGNAL ;
    PORT
      LAYER METAL2 ;
        RECT 68.24 0.0 69.64 0.68 ;
    END
  END SR_int_0_Q2
  PIN sample_nxt_rw
    DIRECTION INOUT ;
    USE SIGNAL ;
    PORT
      LAYER METAL2 ;
        RECT 57.17 43.32 58.57 44.0 ;
    END
  END sample_nxt_rw
  PIN SR_int_0_Q<1>
    DIRECTION INOUT ;
    USE SIGNAL ;
    PORT
      LAYER METAL2 ;
        RECT 52.22 0.0 53.62 0.68 ;
    END
  END SR_int_0_Q<1>
  PIN Readout_flag_gt
    DIRECTION INOUT ;
    USE SIGNAL ;
    PORT
      LAYER METAL2 ;
        RECT 75.75 0.0 77.15 0.68 ;
    END
  END Readout_flag_gt
  PIN Global_rst_b
    DIRECTION INOUT ;
    USE SIGNAL ;
    PORT
      LAYER METAL1 ;
        RECT 115.68 25.31 116.36 26.71 ;
    END
  END Global_rst_b
  PIN int_rst<1>
    DIRECTION INOUT ;
    USE SIGNAL ;
    PORT
      LAYER METAL1 ;
        RECT 115.68 34.95 116.36 36.35 ;
    END
  END int_rst<1>
  PIN DVDD
    DIRECTION INOUT ;
    USE SIGNAL ;
    PORT
      LAYER METAL1 ;
        RECT 115.68 15.9 116.36 17.91 ;
    END
  END DVDD
  PIN GND
    DIRECTION INOUT ;
    USE SIGNAL ;
    PORT
      LAYER METAL1 ;
        RECT 115.68 5.68 116.36 7.69 ;
    END
  END GND
  PIN int_rst<0>
    DIRECTION INOUT ;
    USE SIGNAL ;
    PORT
      LAYER METAL1 ;
        RECT 115.68 1.55 116.36 2.95 ;
    END
  END int_rst<0>
END Conv_TopDig

MACRO Integration_fr_AvgPool_core
  PIN GND
    DIRECTION INOUT ;
    USE SIGNAL ;
    PORT
      LAYER METAL1 ;
        RECT 71.84 21.51 73.23 22.0 ;
    END
  END GND
  PIN Q
    DIRECTION INOUT ;
    USE SIGNAL ;
    PORT
      LAYER METAL3 ;
        RECT 1.45 6.24 3.25 7.04 ;
    END
  END Q
  PIN Vd_prog
    DIRECTION INOUT ;
    USE SIGNAL ;
    PORT
      LAYER METAL2 ;
        RECT 0.0 20.43 0.37 21.23 ;
    END
  END Vd_prog
  PIN int_rst
    DIRECTION INOUT ;
    USE SIGNAL ;
    PORT
      LAYER METAL2 ;
        RECT 0.0 13.45 0.37 14.25 ;
    END
  END int_rst
  PIN Vint
    DIRECTION INOUT ;
    USE SIGNAL ;
    PORT
      LAYER METAL2 ;
        RECT 0.0 14.95 0.37 15.75 ;
    END
  END Vint
  PIN DVDD
    DIRECTION INOUT ;
    USE SIGNAL ;
    PORT
      LAYER METAL2 ;
        RECT 0.0 11.95 0.37 12.75 ;
    END
  END DVDD
  PIN Din
    DIRECTION INOUT ;
    USE SIGNAL ;
    PORT
      LAYER METAL3 ;
        RECT 1.45 2.15 3.25 2.95 ;
    END
  END Din
  PIN RST_B
    DIRECTION INOUT ;
    USE SIGNAL ;
    PORT
      LAYER METAL1 ;
        RECT 14.55 21.51 15.35 22.0 ;
    END
  END RST_B
  PIN CLK
    DIRECTION INOUT ;
    USE SIGNAL ;
    PORT
      LAYER METAL1 ;
        RECT 13.14 21.51 14.1 22.0 ;
    END
  END CLK
  PIN Vimg_CLK
    DIRECTION INOUT ;
    USE SIGNAL ;
    PORT
      LAYER METAL1 ;
        RECT 27.28 21.51 28.28 22.0 ;
    END
  END Vimg_CLK
  PIN CLKB
    DIRECTION INOUT ;
    USE SIGNAL ;
    PORT
      LAYER METAL1 ;
        RECT 11.61 21.51 12.61 22.0 ;
    END
  END CLKB
  PIN nxt_row<1>
    DIRECTION INOUT ;
    USE SIGNAL ;
    PORT
      LAYER METAL1 ;
        RECT 288.77 21.52 289.77 22.0 ;
    END
  END nxt_row<1>
  PIN AVDD_by_2<1>
    DIRECTION INOUT ;
    USE SIGNAL ;
    PORT
      LAYER METAL1 ;
        RECT 196.16 21.52 197.16 22.0 ;
    END
  END AVDD_by_2<1>
  PIN prog<1>
    DIRECTION INOUT ;
    USE SIGNAL ;
    PORT
      LAYER METAL1 ;
        RECT 193.74 21.52 194.74 22.0 ;
    END
  END prog<1>
  PIN run<1>
    DIRECTION INOUT ;
    USE SIGNAL ;
    PORT
      LAYER METAL1 ;
        RECT 191.34 21.52 192.34 22.0 ;
    END
  END run<1>
  PIN Vg<1>
    DIRECTION INOUT ;
    USE SIGNAL ;
    PORT
      LAYER METAL1 ;
        RECT 188.94 21.52 189.94 22.0 ;
    END
  END Vg<1>
  PIN Vsel_b<1>
    DIRECTION INOUT ;
    USE SIGNAL ;
    PORT
      LAYER METAL1 ;
        RECT 186.44 21.51 187.44 22.0 ;
    END
  END Vsel_b<1>
  PIN VINJ<1>
    DIRECTION INOUT ;
    USE SIGNAL ;
    PORT
      LAYER METAL1 ;
        RECT 176.33 21.51 177.33 22.0 ;
    END
  END VINJ<1>
  PIN VTUN
    DIRECTION INOUT ;
    USE SIGNAL ;
    PORT
      LAYER METAL1 ;
        RECT 167.37 21.51 168.37 22.0 ;
    END
  END VTUN
  PIN VINJ<0>
    DIRECTION INOUT ;
    USE SIGNAL ;
    PORT
      LAYER METAL1 ;
        RECT 158.43 21.51 159.43 22.0 ;
    END
  END VINJ<0>
  PIN Vsel_b<0>
    DIRECTION INOUT ;
    USE SIGNAL ;
    PORT
      LAYER METAL1 ;
        RECT 148.32 21.51 149.32 22.0 ;
    END
  END Vsel_b<0>
  PIN Vg<0>
    DIRECTION INOUT ;
    USE SIGNAL ;
    PORT
      LAYER METAL1 ;
        RECT 145.82 21.51 146.82 22.0 ;
    END
  END Vg<0>
  PIN run<0>
    DIRECTION INOUT ;
    USE SIGNAL ;
    PORT
      LAYER METAL1 ;
        RECT 143.42 21.51 144.42 22.0 ;
    END
  END run<0>
  PIN prog<0>
    DIRECTION INOUT ;
    USE SIGNAL ;
    PORT
      LAYER METAL1 ;
        RECT 141.02 21.51 142.02 22.0 ;
    END
  END prog<0>
  PIN AVDD_by_2<0>
    DIRECTION INOUT ;
    USE SIGNAL ;
    PORT
      LAYER METAL1 ;
        RECT 138.6 21.51 139.6 22.0 ;
    END
  END AVDD_by_2<0>
  PIN nxt_row<0>
    DIRECTION INOUT ;
    USE SIGNAL ;
    PORT
      LAYER METAL1 ;
        RECT 45.99 21.51 46.99 22.0 ;
    END
  END nxt_row<0>
END Integration_fr_AvgPool_core

MACRO I_Subtractor_Conv_top
  PIN I_m
    DIRECTION INOUT ;
    USE SIGNAL ;
    PORT
      LAYER METAL2 ;
        RECT 0.0 12.7 0.37 13.7 ;
    END
  END I_m
  PIN Vint
    DIRECTION INOUT ;
    USE SIGNAL ;
    PORT
      LAYER METAL2 ;
        RECT 0.0 16.27 0.37 17.27 ;
    END
  END Vint
  PIN Read_flag_out
    DIRECTION INOUT ;
    USE SIGNAL ;
    PORT
      LAYER METAL2 ;
        RECT 31.12 18.1 31.49 18.9 ;
    END
  END Read_flag_out
  PIN GND
    DIRECTION INOUT ;
    USE SIGNAL ;
    PORT
      LAYER METAL1 ;
        RECT 10.68 20.78 18.71 21.76 ;
    END
  END GND
  PIN Readout_flag_in
    DIRECTION INOUT ;
    USE SIGNAL ;
    PORT
      LAYER METAL1 ;
        RECT 29.72 21.45 30.72 22.0 ;
    END
  END Readout_flag_in
END I_Subtractor_Conv_top

MACRO I_Subtractor_AvgPool_top
  PIN I_m
    DIRECTION INOUT ;
    USE SIGNAL ;
    PORT
      LAYER METAL2 ;
        RECT 0.0 12.7 0.37 13.7 ;
    END
  END I_m
  PIN Vd_prog_krnl
    DIRECTION INOUT ;
    USE SIGNAL ;
    PORT
      LAYER METAL2 ;
        RECT 0.0 18.88 0.37 19.88 ;
    END
  END Vd_prog_krnl
  PIN Vd_prog_avg_pool
    DIRECTION INOUT ;
    USE SIGNAL ;
    PORT
      LAYER METAL2 ;
        RECT 38.54 20.43 38.91 21.23 ;
    END
  END Vd_prog_avg_pool
  PIN Vint
    DIRECTION INOUT ;
    USE SIGNAL ;
    PORT
      LAYER METAL2 ;
        RECT 0.0 16.27 0.37 17.27 ;
    END
  END Vint
  PIN GND
    DIRECTION INOUT ;
    USE SIGNAL ;
    PORT
      LAYER METAL1 ;
        RECT 12.02 21.54 17.24 22.0 ;
    END
  END GND
  PIN run_hv
    DIRECTION INOUT ;
    USE SIGNAL ;
    PORT
      LAYER METAL1 ;
        RECT 36.65 21.54 37.65 22.0 ;
    END
  END run_hv
  PIN VINJ
    DIRECTION INOUT ;
    USE SIGNAL ;
    PORT
      LAYER METAL1 ;
        RECT 31.8 21.54 32.8 22.0 ;
    END
  END VINJ
  PIN prog_hv
    DIRECTION INOUT ;
    USE SIGNAL ;
    PORT
      LAYER METAL1 ;
        RECT 29.8 21.54 30.8 22.0 ;
    END
  END prog_hv
END I_Subtractor_AvgPool_top

MACRO Routes_GateDecodeSwc
  PIN AVDD
    DIRECTION INOUT ;
    USE SIGNAL ;
    PORT
      LAYER METAL1 ;
        RECT 0.0 5.4 0.37 5.9 ;
    END
  END AVDD
END Routes_GateDecodeSwc

MACRO Flatten_Conv_nxtrw_b
  PIN GND
    DIRECTION INOUT ;
    USE SIGNAL ;
    PORT
      LAYER METAL2 ;
        RECT 106.72 3.51 107.18 4.91 ;
    END
  END GND
  PIN nxt_rw
    DIRECTION INOUT ;
    USE SIGNAL ;
    PORT
      LAYER METAL1 ;
        RECT 1.76 21.57 2.76 22.0 ;
    END
  END nxt_rw
  PIN Vb
    DIRECTION INOUT ;
    USE SIGNAL ;
    PORT
      LAYER METAL1 ;
        RECT 34.96 21.57 35.96 22.0 ;
    END
  END Vb
  PIN DVDD
    DIRECTION INOUT ;
    USE SIGNAL ;
    PORT
      LAYER METAL1 ;
        RECT 37.46 21.57 38.46 22.0 ;
    END
  END DVDD
  PIN Vinp
    DIRECTION INOUT ;
    USE SIGNAL ;
    PORT
      LAYER METAL2 ;
        RECT 106.72 0.99 107.18 2.39 ;
    END
  END Vinp
  PIN Q_1_out
    DIRECTION INOUT ;
    USE SIGNAL ;
    PORT
      LAYER METAL2 ;
        RECT 0.0 5.66 0.46 6.66 ;
    END
  END Q_1_out
  PIN Q_1_in
    DIRECTION INOUT ;
    USE SIGNAL ;
    PORT
      LAYER METAL2 ;
        RECT 106.46 5.66 107.18 7.89 ;
    END
  END Q_1_in
  PIN sample
    DIRECTION INOUT ;
    USE SIGNAL ;
    PORT
      LAYER METAL3 ;
        RECT 7.18 12.01 8.98 12.81 ;
    END
  END sample
  PIN Sub_img_out
    DIRECTION INOUT ;
    USE SIGNAL ;
    PORT
      LAYER METAL3 ;
        RECT 97.08 19.0 99.02 20.0 ;
    END
  END Sub_img_out
END Flatten_Conv_nxtrw_b

MACRO TSMC350nm_4x2_Indirect
  PIN Vg<1>
    DIRECTION INOUT ;
    USE SIGNAL ;
    PORT
      LAYER METAL2 ;
        RECT 18.2 21.06 18.8 22.0 ;
    END
  END Vg<1>
  PIN Vsel<1>
    DIRECTION INOUT ;
    USE SIGNAL ;
    PORT
      LAYER METAL2 ;
        RECT 20.3 21.08 20.9 22.0 ;
    END
  END Vsel<1>
  PIN VINJ<1>
    DIRECTION INOUT ;
    USE SIGNAL ;
    PORT
      LAYER METAL2 ;
        RECT 22.4 21.05 23.0 22.0 ;
    END
  END VINJ<1>
  PIN Vsel<0>
    DIRECTION INOUT ;
    USE SIGNAL ;
    PORT
      LAYER METAL2 ;
        RECT 6.3 21.2 6.9 22.0 ;
    END
  END Vsel<0>
  PIN Vs<0>
    DIRECTION INOUT ;
    USE SIGNAL ;
    PORT
      LAYER METAL2 ;
        RECT 2.1 21.21 2.7 22.0 ;
    END
  END Vs<0>
  PIN Vs<1>
    DIRECTION INOUT ;
    USE SIGNAL ;
    PORT
      LAYER METAL2 ;
        RECT 24.5 21.06 25.1 22.0 ;
    END
  END Vs<1>
  PIN VTUN
    DIRECTION INOUT ;
    USE SIGNAL ;
    PORT
      LAYER METAL2 ;
        RECT 13.3 21.09 13.9 22.0 ;
    END
  END VTUN
  PIN VINJ<0>
    DIRECTION INOUT ;
    USE SIGNAL ;
    PORT
      LAYER METAL2 ;
        RECT 4.2 21.18 4.8 22.0 ;
    END
  END VINJ<0>
  PIN GND<0>
    DIRECTION INOUT ;
    USE SIGNAL ;
    PORT
      LAYER METAL2 ;
        RECT 11.2 21.07 11.8 22.0 ;
    END
  END GND<0>
  PIN Vg<0>
    DIRECTION INOUT ;
    USE SIGNAL ;
    PORT
      LAYER METAL2 ;
        RECT 8.4 21.03 9.0 22.0 ;
    END
  END Vg<0>
  PIN GND<1>
    DIRECTION INOUT ;
    USE SIGNAL ;
    PORT
      LAYER METAL2 ;
        RECT 15.41 21.06 16.01 22.0 ;
    END
  END GND<1>
  PIN Vs_b<0>
    DIRECTION INOUT ;
    USE SIGNAL ;
    PORT
      LAYER METAL2 ;
        RECT 1.42 0.0 2.7 0.6 ;
    END
  END Vs_b<0>
  PIN VINJ_b<0>
    DIRECTION INOUT ;
    USE SIGNAL ;
    PORT
      LAYER METAL2 ;
        RECT 4.2 0.0 4.8 0.76 ;
    END
  END VINJ_b<0>
  PIN Vsel_b<0>
    DIRECTION INOUT ;
    USE SIGNAL ;
    PORT
      LAYER METAL2 ;
        RECT 6.3 0.0 6.9 0.78 ;
    END
  END Vsel_b<0>
  PIN Vg_b<0>
    DIRECTION INOUT ;
    USE SIGNAL ;
    PORT
      LAYER METAL2 ;
        RECT 8.4 0.0 9.0 0.77 ;
    END
  END Vg_b<0>
  PIN GND_b<0>
    DIRECTION INOUT ;
    USE SIGNAL ;
    PORT
      LAYER METAL2 ;
        RECT 11.2 0.0 11.8 0.76 ;
    END
  END GND_b<0>
  PIN VTUN_b
    DIRECTION INOUT ;
    USE SIGNAL ;
    PORT
      LAYER METAL2 ;
        RECT 13.3 0.0 13.9 0.76 ;
    END
  END VTUN_b
  PIN GND_b<1>
    DIRECTION INOUT ;
    USE SIGNAL ;
    PORT
      LAYER METAL2 ;
        RECT 15.41 0.0 16.01 0.83 ;
    END
  END GND_b<1>
  PIN Vg_b<1>
    DIRECTION INOUT ;
    USE SIGNAL ;
    PORT
      LAYER METAL2 ;
        RECT 18.2 0.0 18.8 0.76 ;
    END
  END Vg_b<1>
  PIN Vsel_b<1>
    DIRECTION INOUT ;
    USE SIGNAL ;
    PORT
      LAYER METAL2 ;
        RECT 20.3 0.0 20.9 0.75 ;
    END
  END Vsel_b<1>
  PIN VINJ_b<1>
    DIRECTION INOUT ;
    USE SIGNAL ;
    PORT
      LAYER METAL2 ;
        RECT 22.4 0.0 23.0 0.77 ;
    END
  END VINJ_b<1>
  PIN Vs_b<1>
    DIRECTION INOUT ;
    USE SIGNAL ;
    PORT
      LAYER METAL2 ;
        RECT 24.5 0.0 25.75 0.61 ;
    END
  END Vs_b<1>
  PIN Vd_Pl<3>
    DIRECTION INOUT ;
    USE SIGNAL ;
    PORT
      LAYER METAL1 ;
        RECT 0.0 0.7 1.47 1.2 ;
    END
  END Vd_Pl<3>
  PIN Vd_Rl<3>
    DIRECTION INOUT ;
    USE SIGNAL ;
    PORT
      LAYER METAL1 ;
        RECT 0.0 3.5 1.45 4.0 ;
    END
  END Vd_Rl<3>
  PIN Vd_Rl<2>
    DIRECTION INOUT ;
    USE SIGNAL ;
    PORT
      LAYER METAL1 ;
        RECT 0.0 7.0 1.4 7.5 ;
    END
  END Vd_Rl<2>
  PIN Vd_Pl<2>
    DIRECTION INOUT ;
    USE SIGNAL ;
    PORT
      LAYER METAL1 ;
        RECT 0.0 9.8 1.41 10.3 ;
    END
  END Vd_Pl<2>
  PIN Vd_Pl<1>
    DIRECTION INOUT ;
    USE SIGNAL ;
    PORT
      LAYER METAL1 ;
        RECT 0.0 11.89 1.43 12.4 ;
    END
  END Vd_Pl<1>
  PIN Vd_Rl<1>
    DIRECTION INOUT ;
    USE SIGNAL ;
    PORT
      LAYER METAL1 ;
        RECT 0.0 14.7 1.46 15.2 ;
    END
  END Vd_Rl<1>
  PIN Vd_Rl<0>
    DIRECTION INOUT ;
    USE SIGNAL ;
    PORT
      LAYER METAL1 ;
        RECT 0.0 17.5 1.43 18.0 ;
    END
  END Vd_Rl<0>
  PIN Vd_Pl<0>
    DIRECTION INOUT ;
    USE SIGNAL ;
    PORT
      LAYER METAL1 ;
        RECT 0.0 20.3 1.4 20.9 ;
    END
  END Vd_Pl<0>
  PIN Vd_P<0>
    DIRECTION INOUT ;
    USE SIGNAL ;
    PORT
      LAYER METAL1 ;
        RECT 26.63 20.3 27.46 20.8 ;
    END
  END Vd_P<0>
  PIN Vd_R<1>
    DIRECTION INOUT ;
    USE SIGNAL ;
    PORT
      LAYER METAL1 ;
        RECT 26.56 14.7 27.44 15.2 ;
    END
  END Vd_R<1>
  PIN Vd_R<3>
    DIRECTION INOUT ;
    USE SIGNAL ;
    PORT
      LAYER METAL1 ;
        RECT 26.5 3.5 27.46 4.0 ;
    END
  END Vd_R<3>
  PIN Vd_P<3>
    DIRECTION INOUT ;
    USE SIGNAL ;
    PORT
      LAYER METAL1 ;
        RECT 26.55 0.7 27.46 1.2 ;
    END
  END Vd_P<3>
  PIN Vd_P<1>
    DIRECTION INOUT ;
    USE SIGNAL ;
    PORT
      LAYER METAL1 ;
        RECT 26.38 11.9 27.46 12.4 ;
    END
  END Vd_P<1>
  PIN Vd_P<2>
    DIRECTION INOUT ;
    USE SIGNAL ;
    PORT
      LAYER METAL1 ;
        RECT 26.51 9.8 27.46 10.3 ;
    END
  END Vd_P<2>
  PIN Vd_R<0>
    DIRECTION INOUT ;
    USE SIGNAL ;
    PORT
      LAYER METAL1 ;
        RECT 26.66 17.5 27.46 18.0 ;
    END
  END Vd_R<0>
  PIN Vd_R<2>
    DIRECTION INOUT ;
    USE SIGNAL ;
    PORT
      LAYER METAL1 ;
        RECT 26.53 7.0 27.46 7.5 ;
    END
  END Vd_R<2>
END TSMC350nm_4x2_Indirect

MACRO Flatten_Conv_nxtrw
  PIN Vinp
    DIRECTION INOUT ;
    USE SIGNAL ;
    PORT
      LAYER METAL2 ;
        RECT 0.0 0.99 0.46 1.99 ;
    END
  END Vinp
  PIN GND
    DIRECTION INOUT ;
    USE SIGNAL ;
    PORT
      LAYER METAL1 ;
        RECT 29.09 21.57 30.09 22.0 ;
    END
  END GND
  PIN Q_1_out
    DIRECTION INOUT ;
    USE SIGNAL ;
    PORT
      LAYER METAL2 ;
        RECT 0.0 5.66 0.46 6.66 ;
    END
  END Q_1_out
  PIN Q_1_in
    DIRECTION INOUT ;
    USE SIGNAL ;
    PORT
      LAYER METAL2 ;
        RECT 103.09 5.55 103.81 7.78 ;
    END
  END Q_1_in
  PIN nxt_rw
    DIRECTION INOUT ;
    USE SIGNAL ;
    PORT
      LAYER METAL1 ;
        RECT 1.76 21.57 2.76 22.0 ;
    END
  END nxt_rw
  PIN DVDD
    DIRECTION INOUT ;
    USE SIGNAL ;
    PORT
      LAYER METAL1 ;
        RECT 34.09 21.57 35.09 22.0 ;
    END
  END DVDD
  PIN Vb
    DIRECTION INOUT ;
    USE SIGNAL ;
    PORT
      LAYER METAL1 ;
        RECT 31.59 21.57 32.59 22.0 ;
    END
  END Vb
  PIN Sub_img_out
    DIRECTION INOUT ;
    USE SIGNAL ;
    PORT
      LAYER METAL3 ;
        RECT 93.71 19.0 95.65 20.0 ;
    END
  END Sub_img_out
  PIN sample
    DIRECTION INOUT ;
    USE SIGNAL ;
    PORT
      LAYER METAL3 ;
        RECT 3.81 12.01 5.61 12.81 ;
    END
  END sample
END Flatten_Conv_nxtrw

MACRO Integration_fr_AvgPool_start
  PIN GND
    DIRECTION INOUT ;
    USE SIGNAL ;
    PORT
      LAYER METAL1 ;
        RECT 71.84 21.51 73.23 22.0 ;
    END
  END GND
  PIN Q
    DIRECTION INOUT ;
    USE SIGNAL ;
    PORT
      LAYER METAL3 ;
        RECT 1.45 6.24 3.25 7.04 ;
    END
  END Q
  PIN Vd_prog
    DIRECTION INOUT ;
    USE SIGNAL ;
    PORT
      LAYER METAL2 ;
        RECT 0.0 20.43 0.37 21.23 ;
    END
  END Vd_prog
  PIN int_rst
    DIRECTION INOUT ;
    USE SIGNAL ;
    PORT
      LAYER METAL2 ;
        RECT 0.0 13.45 0.37 14.25 ;
    END
  END int_rst
  PIN Vint
    DIRECTION INOUT ;
    USE SIGNAL ;
    PORT
      LAYER METAL2 ;
        RECT 0.0 14.95 0.37 15.75 ;
    END
  END Vint
  PIN DVDD
    DIRECTION INOUT ;
    USE SIGNAL ;
    PORT
      LAYER METAL2 ;
        RECT 0.0 11.95 0.37 12.75 ;
    END
  END DVDD
  PIN Din
    DIRECTION INOUT ;
    USE SIGNAL ;
    PORT
      LAYER METAL3 ;
        RECT 1.45 2.15 3.25 2.95 ;
    END
  END Din
  PIN RST_B
    DIRECTION INOUT ;
    USE SIGNAL ;
    PORT
      LAYER METAL1 ;
        RECT 14.55 21.51 15.35 22.0 ;
    END
  END RST_B
  PIN CLK
    DIRECTION INOUT ;
    USE SIGNAL ;
    PORT
      LAYER METAL1 ;
        RECT 13.14 21.51 14.1 22.0 ;
    END
  END CLK
  PIN Vimg_CLK
    DIRECTION INOUT ;
    USE SIGNAL ;
    PORT
      LAYER METAL1 ;
        RECT 27.28 21.51 28.28 22.0 ;
    END
  END Vimg_CLK
  PIN CLKB
    DIRECTION INOUT ;
    USE SIGNAL ;
    PORT
      LAYER METAL1 ;
        RECT 11.61 21.51 12.61 22.0 ;
    END
  END CLKB
  PIN nxt_row<1>
    DIRECTION INOUT ;
    USE SIGNAL ;
    PORT
      LAYER METAL1 ;
        RECT 288.77 21.52 289.77 22.0 ;
    END
  END nxt_row<1>
  PIN AVDD_by_2<1>
    DIRECTION INOUT ;
    USE SIGNAL ;
    PORT
      LAYER METAL1 ;
        RECT 196.16 21.52 197.16 22.0 ;
    END
  END AVDD_by_2<1>
  PIN prog<1>
    DIRECTION INOUT ;
    USE SIGNAL ;
    PORT
      LAYER METAL1 ;
        RECT 193.74 21.52 194.74 22.0 ;
    END
  END prog<1>
  PIN run<1>
    DIRECTION INOUT ;
    USE SIGNAL ;
    PORT
      LAYER METAL1 ;
        RECT 191.34 21.52 192.34 22.0 ;
    END
  END run<1>
  PIN Vg<1>
    DIRECTION INOUT ;
    USE SIGNAL ;
    PORT
      LAYER METAL1 ;
        RECT 188.94 21.52 189.94 22.0 ;
    END
  END Vg<1>
  PIN Vsel_b<1>
    DIRECTION INOUT ;
    USE SIGNAL ;
    PORT
      LAYER METAL1 ;
        RECT 186.44 21.51 187.44 22.0 ;
    END
  END Vsel_b<1>
  PIN VINJ<1>
    DIRECTION INOUT ;
    USE SIGNAL ;
    PORT
      LAYER METAL1 ;
        RECT 176.33 21.51 177.33 22.0 ;
    END
  END VINJ<1>
  PIN VTUN
    DIRECTION INOUT ;
    USE SIGNAL ;
    PORT
      LAYER METAL1 ;
        RECT 167.37 21.51 168.37 22.0 ;
    END
  END VTUN
  PIN VINJ<0>
    DIRECTION INOUT ;
    USE SIGNAL ;
    PORT
      LAYER METAL1 ;
        RECT 158.43 21.51 159.43 22.0 ;
    END
  END VINJ<0>
  PIN Vsel_b<0>
    DIRECTION INOUT ;
    USE SIGNAL ;
    PORT
      LAYER METAL1 ;
        RECT 148.32 21.51 149.32 22.0 ;
    END
  END Vsel_b<0>
  PIN Vg<0>
    DIRECTION INOUT ;
    USE SIGNAL ;
    PORT
      LAYER METAL1 ;
        RECT 145.82 21.51 146.82 22.0 ;
    END
  END Vg<0>
  PIN run<0>
    DIRECTION INOUT ;
    USE SIGNAL ;
    PORT
      LAYER METAL1 ;
        RECT 143.42 21.51 144.42 22.0 ;
    END
  END run<0>
  PIN prog<0>
    DIRECTION INOUT ;
    USE SIGNAL ;
    PORT
      LAYER METAL1 ;
        RECT 141.02 21.51 142.02 22.0 ;
    END
  END prog<0>
  PIN AVDD_by_2<0>
    DIRECTION INOUT ;
    USE SIGNAL ;
    PORT
      LAYER METAL1 ;
        RECT 138.6 21.51 139.6 22.0 ;
    END
  END AVDD_by_2<0>
  PIN nxt_row<0>
    DIRECTION INOUT ;
    USE SIGNAL ;
    PORT
      LAYER METAL1 ;
        RECT 45.99 21.51 46.99 22.0 ;
    END
  END nxt_row<0>
END Integration_fr_AvgPool_start

MACRO Tgate_swc_fr_Kernel_Horiz_bot_only
  PIN Q
    DIRECTION INOUT ;
    USE SIGNAL ;
    PORT
      LAYER METAL2 ;
        RECT 30.34 1.93 30.62 2.53 ;
    END
  END Q
  PIN GND
    DIRECTION INOUT ;
    USE SIGNAL ;
    PORT
      LAYER METAL1 ;
        RECT 30.84 21.37 31.64 22.0 ;
    END
  END GND
  PIN Final_row_out
    DIRECTION INOUT ;
    USE SIGNAL ;
    PORT
      LAYER METAL2 ;
        RECT 56.59 2.61 56.93 3.41 ;
    END
  END Final_row_out
  PIN I_m
    DIRECTION INOUT ;
    USE SIGNAL ;
    PORT
      LAYER METAL2 ;
        RECT 56.26 12.7 56.93 13.7 ;
    END
  END I_m
  PIN I_p
    DIRECTION INOUT ;
    USE SIGNAL ;
    PORT
      LAYER METAL2 ;
        RECT 56.26 16.27 56.93 17.27 ;
    END
  END I_p
  PIN Vd<0>
    DIRECTION INOUT ;
    USE SIGNAL ;
    PORT
      LAYER METAL1 ;
        RECT 0.0 17.5 0.42 18.2 ;
    END
  END Vd<0>
  PIN RUN_HV
    DIRECTION INOUT ;
    USE SIGNAL ;
    PORT
      LAYER METAL2 ;
        RECT 23.12 21.33 23.92 22.0 ;
    END
  END RUN_HV
  PIN VINJ
    DIRECTION INOUT ;
    USE SIGNAL ;
    PORT
      LAYER METAL2 ;
        RECT 9.08 21.33 10.08 22.0 ;
    END
  END VINJ
  PIN Vd_prog_0_out
    DIRECTION INOUT ;
    USE SIGNAL ;
    PORT
      LAYER METAL2 ;
        RECT 56.26 18.87 56.93 19.87 ;
    END
  END Vd_prog_0_out
  PIN Din_Glb
    DIRECTION INOUT ;
    USE SIGNAL ;
    PORT
      LAYER METAL1 ;
        RECT 54.82 21.4 55.62 22.0 ;
    END
  END Din_Glb
  PIN Final_rw_out
    DIRECTION INOUT ;
    USE SIGNAL ;
    PORT
      LAYER METAL1 ;
        RECT 52.52 21.4 53.32 22.0 ;
    END
  END Final_rw_out
  PIN Final_rw_in
    DIRECTION INOUT ;
    USE SIGNAL ;
    PORT
      LAYER METAL1 ;
        RECT 52.52 1.88 53.32 2.48 ;
    END
  END Final_rw_in
  PIN Vd_prog_0_in
    DIRECTION INOUT ;
    USE SIGNAL ;
    PORT
      LAYER METAL1 ;
        RECT 0.0 20.3 0.41 20.8 ;
    END
  END Vd_prog_0_in
  PIN DVDD
    DIRECTION INOUT ;
    USE SIGNAL ;
    PORT
      LAYER METAL1 ;
        RECT 43.41 21.37 44.11 22.0 ;
    END
  END DVDD
  PIN RSTB
    DIRECTION INOUT ;
    USE SIGNAL ;
    PORT
      LAYER METAL1 ;
        RECT 40.9 21.37 41.6 22.0 ;
    END
  END RSTB
  PIN CLK
    DIRECTION INOUT ;
    USE SIGNAL ;
    PORT
      LAYER METAL1 ;
        RECT 39.49 21.37 40.19 22.0 ;
    END
  END CLK
  PIN CLKB
    DIRECTION INOUT ;
    USE SIGNAL ;
    PORT
      LAYER METAL1 ;
        RECT 38.26 21.37 38.96 22.0 ;
    END
  END CLKB
  PIN Vd<3>
    DIRECTION INOUT ;
    USE SIGNAL ;
    PORT
      LAYER METAL1 ;
        RECT 0.0 3.3 0.42 4.0 ;
    END
  END Vd<3>
  PIN Vd<2>
    DIRECTION INOUT ;
    USE SIGNAL ;
    PORT
      LAYER METAL1 ;
        RECT 0.0 6.33 0.42 7.03 ;
    END
  END Vd<2>
  PIN Vd<1>
    DIRECTION INOUT ;
    USE SIGNAL ;
    PORT
      LAYER METAL1 ;
        RECT 0.0 14.5 0.42 15.2 ;
    END
  END Vd<1>
END Tgate_swc_fr_Kernel_Horiz_bot_only

MACRO AvgPool_n_Relu
  PIN Sub_img_out
    DIRECTION INOUT ;
    USE SIGNAL ;
    PORT
      LAYER METAL2 ;
        RECT 96.62 7.23 96.99 8.43 ;
    END
  END Sub_img_out
  PIN Out_En_b
    DIRECTION INOUT ;
    USE SIGNAL ;
    PORT
      LAYER METAL2 ;
        RECT 96.62 5.03 96.99 5.83 ;
    END
  END Out_En_b
  PIN Vd_prog
    DIRECTION INOUT ;
    USE SIGNAL ;
    PORT
      LAYER METAL2 ;
        RECT 0.0 20.43 0.37 21.23 ;
    END
  END Vd_prog
  PIN int_rst_out
    DIRECTION INOUT ;
    USE SIGNAL ;
    PORT
      LAYER METAL2 ;
        RECT 96.62 12.03 96.99 12.83 ;
    END
  END int_rst_out
  PIN Vint_out
    DIRECTION INOUT ;
    USE SIGNAL ;
    PORT
      LAYER METAL2 ;
        RECT 96.62 14.95 96.99 15.75 ;
    END
  END Vint_out
  PIN DVDD
    DIRECTION INOUT ;
    USE SIGNAL ;
    PORT
      LAYER METAL2 ;
        RECT 0.0 11.95 0.37 12.75 ;
    END
  END DVDD
  PIN Q_out
    DIRECTION INOUT ;
    USE SIGNAL ;
    PORT
      LAYER METAL2 ;
        RECT 96.62 2.83 96.99 3.63 ;
    END
  END Q_out
  PIN GND
    DIRECTION INOUT ;
    USE SIGNAL ;
    PORT
      LAYER METAL2 ;
        RECT 96.62 17.15 96.99 18.35 ;
    END
  END GND
  PIN Q_in
    DIRECTION INOUT ;
    USE SIGNAL ;
    PORT
      LAYER METAL2 ;
        RECT 0.0 2.15 0.37 2.95 ;
    END
  END Q_in
  PIN Vint_in
    DIRECTION INOUT ;
    USE SIGNAL ;
    PORT
      LAYER METAL2 ;
        RECT 0.0 14.95 0.37 15.75 ;
    END
  END Vint_in
  PIN int_rst_in
    DIRECTION INOUT ;
    USE SIGNAL ;
    PORT
      LAYER METAL2 ;
        RECT 0.0 13.45 0.37 14.25 ;
    END
  END int_rst_in
  PIN VINJ
    DIRECTION INOUT ;
    USE SIGNAL ;
    PORT
      LAYER METAL1 ;
        RECT 10.53 21.53 11.53 22.0 ;
    END
  END VINJ
  PIN AVDD
    DIRECTION INOUT ;
    USE SIGNAL ;
    PORT
      LAYER METAL1 ;
        RECT 82.71 21.53 83.71 22.0 ;
    END
  END AVDD
  PIN Vb
    DIRECTION INOUT ;
    USE SIGNAL ;
    PORT
      LAYER METAL1 ;
        RECT 54.49 21.53 55.49 22.0 ;
    END
  END Vb
  PIN run_hv
    DIRECTION INOUT ;
    USE SIGNAL ;
    PORT
      LAYER METAL1 ;
        RECT 8.03 21.53 9.03 22.0 ;
    END
  END run_hv
  PIN prog_hv
    DIRECTION INOUT ;
    USE SIGNAL ;
    PORT
      LAYER METAL1 ;
        RECT 5.63 21.53 6.63 22.0 ;
    END
  END prog_hv
END AvgPool_n_Relu

MACRO Tgate_swc_fr_Kernel_Horiz_top_edge
  PIN Q_bot
    DIRECTION INOUT ;
    USE SIGNAL ;
    PORT
      LAYER METAL2 ;
        RECT 8.6 0.0 9.2 0.28 ;
    END
  END Q_bot
  PIN GND
    DIRECTION INOUT ;
    USE SIGNAL ;
    PORT
      LAYER METAL1 ;
        RECT 30.84 21.37 31.64 22.0 ;
    END
  END GND
  PIN Din
    DIRECTION INOUT ;
    USE SIGNAL ;
    PORT
      LAYER METAL1 ;
        RECT 0.0 19.48 0.4 20.18 ;
    END
  END Din
  PIN RST_B
    DIRECTION INOUT ;
    USE SIGNAL ;
    PORT
      LAYER METAL1 ;
        RECT 0.0 10.56 0.4 11.26 ;
    END
  END RST_B
  PIN Q
    DIRECTION INOUT ;
    USE SIGNAL ;
    PORT
      LAYER METAL1 ;
        RECT 10.73 19.48 11.13 20.18 ;
    END
  END Q
  PIN DVDD
    DIRECTION INOUT ;
    USE SIGNAL ;
    PORT
      LAYER METAL1 ;
        RECT 43.41 21.37 44.11 22.0 ;
    END
  END DVDD
  PIN CLK
    DIRECTION INOUT ;
    USE SIGNAL ;
    PORT
      LAYER METAL1 ;
        RECT 39.49 21.37 40.19 22.0 ;
    END
  END CLK
  PIN CLKB
    DIRECTION INOUT ;
    USE SIGNAL ;
    PORT
      LAYER METAL1 ;
        RECT 38.26 21.37 38.96 22.0 ;
    END
  END CLKB
  PIN Final_row_out
    DIRECTION INOUT ;
    USE SIGNAL ;
    PORT
      LAYER METAL2 ;
        RECT 56.59 2.61 56.93 3.41 ;
    END
  END Final_row_out
  PIN I_m
    DIRECTION INOUT ;
    USE SIGNAL ;
    PORT
      LAYER METAL2 ;
        RECT 56.26 12.7 56.93 13.7 ;
    END
  END I_m
  PIN I_p
    DIRECTION INOUT ;
    USE SIGNAL ;
    PORT
      LAYER METAL2 ;
        RECT 56.26 16.27 56.93 17.27 ;
    END
  END I_p
  PIN Vd<0>
    DIRECTION INOUT ;
    USE SIGNAL ;
    PORT
      LAYER METAL1 ;
        RECT 0.0 17.5 0.42 18.2 ;
    END
  END Vd<0>
  PIN RUN_HV
    DIRECTION INOUT ;
    USE SIGNAL ;
    PORT
      LAYER METAL2 ;
        RECT 23.12 21.33 23.92 22.0 ;
    END
  END RUN_HV
  PIN VINJ
    DIRECTION INOUT ;
    USE SIGNAL ;
    PORT
      LAYER METAL2 ;
        RECT 9.08 21.33 10.08 22.0 ;
    END
  END VINJ
  PIN Vd_prog_0_out
    DIRECTION INOUT ;
    USE SIGNAL ;
    PORT
      LAYER METAL2 ;
        RECT 56.26 18.87 56.93 19.87 ;
    END
  END Vd_prog_0_out
  PIN Din_Glb
    DIRECTION INOUT ;
    USE SIGNAL ;
    PORT
      LAYER METAL1 ;
        RECT 54.82 21.4 55.62 22.0 ;
    END
  END Din_Glb
  PIN Final_rw_out
    DIRECTION INOUT ;
    USE SIGNAL ;
    PORT
      LAYER METAL1 ;
        RECT 52.52 21.4 53.32 22.0 ;
    END
  END Final_rw_out
  PIN Final_rw_in
    DIRECTION INOUT ;
    USE SIGNAL ;
    PORT
      LAYER METAL1 ;
        RECT 52.52 0.0 53.32 0.6 ;
    END
  END Final_rw_in
  PIN Vd_prog_0_in
    DIRECTION INOUT ;
    USE SIGNAL ;
    PORT
      LAYER METAL1 ;
        RECT 0.0 20.3 0.41 20.8 ;
    END
  END Vd_prog_0_in
  PIN Q<1>
    DIRECTION INOUT ;
    USE SIGNAL ;
    PORT
      LAYER METAL1 ;
        RECT 49.82 0.0 50.52 0.63 ;
    END
  END Q<1>
  PIN RSTB
    DIRECTION INOUT ;
    USE SIGNAL ;
    PORT
      LAYER METAL1 ;
        RECT 40.9 21.37 41.6 22.0 ;
    END
  END RSTB
  PIN Vd<3>
    DIRECTION INOUT ;
    USE SIGNAL ;
    PORT
      LAYER METAL1 ;
        RECT 0.0 3.3 0.42 4.0 ;
    END
  END Vd<3>
  PIN Vd<2>
    DIRECTION INOUT ;
    USE SIGNAL ;
    PORT
      LAYER METAL1 ;
        RECT 0.0 6.33 0.42 7.03 ;
    END
  END Vd<2>
  PIN Vd<1>
    DIRECTION INOUT ;
    USE SIGNAL ;
    PORT
      LAYER METAL1 ;
        RECT 0.0 14.5 0.42 15.2 ;
    END
  END Vd<1>
END Tgate_swc_fr_Kernel_Horiz_top_edge

MACRO DynamicShiftReg_Rst_Lo
  PIN Q_bot
    DIRECTION INOUT ;
    USE SIGNAL ;
    PORT
      LAYER METAL2 ;
        RECT 8.6 0.0 9.2 0.28 ;
    END
  END Q_bot
  PIN GND
    DIRECTION INOUT ;
    USE SIGNAL ;
    PORT
      LAYER METAL1 ;
        RECT 0.0 0.5 0.4 1.3 ;
    END
  END GND
  PIN Din
    DIRECTION INOUT ;
    USE SIGNAL ;
    PORT
      LAYER METAL1 ;
        RECT 0.0 19.48 0.4 20.18 ;
    END
  END Din
  PIN RST_B
    DIRECTION INOUT ;
    USE SIGNAL ;
    PORT
      LAYER METAL1 ;
        RECT 0.0 10.56 0.4 11.26 ;
    END
  END RST_B
  PIN Q
    DIRECTION INOUT ;
    USE SIGNAL ;
    PORT
      LAYER METAL1 ;
        RECT 10.73 19.48 11.13 20.18 ;
    END
  END Q
  PIN DVDD
    DIRECTION INOUT ;
    USE SIGNAL ;
    PORT
      LAYER METAL1 ;
        RECT 0.0 13.07 0.4 13.77 ;
    END
  END DVDD
  PIN CLK
    DIRECTION INOUT ;
    USE SIGNAL ;
    PORT
      LAYER METAL1 ;
        RECT 0.0 9.15 0.4 9.85 ;
    END
  END CLK
  PIN CLKB
    DIRECTION INOUT ;
    USE SIGNAL ;
    PORT
      LAYER METAL1 ;
        RECT 0.0 7.92 0.4 8.62 ;
    END
  END CLKB
END DynamicShiftReg_Rst_Lo

MACRO Integration_n_Relu_core
  PIN Final_rw
    DIRECTION INOUT ;
    USE SIGNAL ;
    PORT
      LAYER METAL2 ;
        RECT 0.0 18.1 0.54 18.9 ;
    END
  END Final_rw
  PIN Vint
    DIRECTION INOUT ;
    USE SIGNAL ;
    PORT
      LAYER METAL2 ;
        RECT 0.0 19.5 0.54 20.3 ;
    END
  END Vint
  PIN CLK
    DIRECTION INOUT ;
    USE SIGNAL ;
    PORT
      LAYER METAL1 ;
        RECT 90.13 21.68 91.13 22.0 ;
    END
  END CLK
  PIN Sub_img_out
    DIRECTION INOUT ;
    USE SIGNAL ;
    PORT
      LAYER METAL2 ;
        RECT 0.0 0.99 0.54 1.99 ;
    END
  END Sub_img_out
  PIN GND
    DIRECTION INOUT ;
    USE SIGNAL ;
    PORT
      LAYER METAL1 ;
        RECT 113.67 21.68 115.18 22.0 ;
    END
  END GND
  PIN CLKB
    DIRECTION INOUT ;
    USE SIGNAL ;
    PORT
      LAYER METAL1 ;
        RECT 92.63 21.68 93.63 22.0 ;
    END
  END CLKB
  PIN Q_1
    DIRECTION INOUT ;
    USE SIGNAL ;
    PORT
      LAYER METAL2 ;
        RECT 175.06 5.76 175.6 6.56 ;
    END
  END Q_1
  PIN Q
    DIRECTION INOUT ;
    USE SIGNAL ;
    PORT
      LAYER METAL3 ;
        RECT 1.05 5.76 2.85 6.61 ;
    END
  END Q
  PIN Din
    DIRECTION INOUT ;
    USE SIGNAL ;
    PORT
      LAYER METAL3 ;
        RECT 1.05 13.71 2.85 14.56 ;
    END
  END Din
  PIN RST_B
    DIRECTION INOUT ;
    USE SIGNAL ;
    PORT
      LAYER METAL1 ;
        RECT 11.3 21.68 12.3 22.0 ;
    END
  END RST_B
  PIN DVDD
    DIRECTION INOUT ;
    USE SIGNAL ;
    PORT
      LAYER METAL1 ;
        RECT 39.41 21.68 40.41 22.0 ;
    END
  END DVDD
  PIN VImg_CLK
    DIRECTION INOUT ;
    USE SIGNAL ;
    PORT
      LAYER METAL1 ;
        RECT 41.91 21.68 42.91 22.0 ;
    END
  END VImg_CLK
  PIN Vb
    DIRECTION INOUT ;
    USE SIGNAL ;
    PORT
      LAYER METAL1 ;
        RECT 87.63 21.68 88.63 22.0 ;
    END
  END Vb
  PIN AVDD_by_2
    DIRECTION INOUT ;
    USE SIGNAL ;
    PORT
      LAYER METAL1 ;
        RECT 84.38 21.68 85.38 22.0 ;
    END
  END AVDD_by_2
  PIN AVDD
    DIRECTION INOUT ;
    USE SIGNAL ;
    PORT
      LAYER METAL1 ;
        RECT 80.38 21.68 81.38 22.0 ;
    END
  END AVDD
  PIN Out_En
    DIRECTION INOUT ;
    USE SIGNAL ;
    PORT
      LAYER METAL3 ;
        RECT 66.67 10.43 68.47 11.43 ;
    END
  END Out_En
  PIN int_rst
    DIRECTION INOUT ;
    USE SIGNAL ;
    PORT
      LAYER METAL3 ;
        RECT 82.02 16.58 83.88 17.58 ;
    END
  END int_rst
END Integration_n_Relu_core

MACRO Integration_n_Relu_start
  PIN Final_rw
    DIRECTION INOUT ;
    USE SIGNAL ;
    PORT
      LAYER METAL2 ;
        RECT 0.0 18.1 0.54 18.9 ;
    END
  END Final_rw
  PIN Vint
    DIRECTION INOUT ;
    USE SIGNAL ;
    PORT
      LAYER METAL2 ;
        RECT 0.0 19.5 0.54 20.3 ;
    END
  END Vint
  PIN int_rst
    DIRECTION INOUT ;
    USE SIGNAL ;
    PORT
      LAYER METAL3 ;
        RECT 82.02 16.58 83.88 17.58 ;
    END
  END int_rst
  PIN CLK
    DIRECTION INOUT ;
    USE SIGNAL ;
    PORT
      LAYER METAL1 ;
        RECT 90.13 21.68 91.13 22.0 ;
    END
  END CLK
  PIN Sub_img_out
    DIRECTION INOUT ;
    USE SIGNAL ;
    PORT
      LAYER METAL2 ;
        RECT 0.0 0.99 0.54 1.99 ;
    END
  END Sub_img_out
  PIN GND
    DIRECTION INOUT ;
    USE SIGNAL ;
    PORT
      LAYER METAL1 ;
        RECT 133.36 21.68 134.96 22.0 ;
    END
  END GND
  PIN CLKB
    DIRECTION INOUT ;
    USE SIGNAL ;
    PORT
      LAYER METAL1 ;
        RECT 92.64 21.68 93.64 22.0 ;
    END
  END CLKB
  PIN Q_1
    DIRECTION INOUT ;
    USE SIGNAL ;
    PORT
      LAYER METAL2 ;
        RECT 175.06 5.76 175.6 6.56 ;
    END
  END Q_1
  PIN Q
    DIRECTION INOUT ;
    USE SIGNAL ;
    PORT
      LAYER METAL3 ;
        RECT 1.05 5.76 2.85 6.61 ;
    END
  END Q
  PIN Din
    DIRECTION INOUT ;
    USE SIGNAL ;
    PORT
      LAYER METAL3 ;
        RECT 1.05 13.71 2.85 14.56 ;
    END
  END Din
  PIN RST_B
    DIRECTION INOUT ;
    USE SIGNAL ;
    PORT
      LAYER METAL1 ;
        RECT 11.31 21.68 12.3 22.0 ;
    END
  END RST_B
  PIN DVDD
    DIRECTION INOUT ;
    USE SIGNAL ;
    PORT
      LAYER METAL1 ;
        RECT 39.41 21.68 40.41 22.0 ;
    END
  END DVDD
  PIN VImg_CLK
    DIRECTION INOUT ;
    USE SIGNAL ;
    PORT
      LAYER METAL1 ;
        RECT 41.91 21.68 42.91 22.0 ;
    END
  END VImg_CLK
  PIN Vb
    DIRECTION INOUT ;
    USE SIGNAL ;
    PORT
      LAYER METAL1 ;
        RECT 87.63 21.68 88.63 22.0 ;
    END
  END Vb
  PIN AVDD_by_2
    DIRECTION INOUT ;
    USE SIGNAL ;
    PORT
      LAYER METAL1 ;
        RECT 84.38 21.68 85.38 22.0 ;
    END
  END AVDD_by_2
  PIN AVDD
    DIRECTION INOUT ;
    USE SIGNAL ;
    PORT
      LAYER METAL1 ;
        RECT 80.38 21.68 81.38 22.0 ;
    END
  END AVDD
  PIN Out_En
    DIRECTION INOUT ;
    USE SIGNAL ;
    PORT
      LAYER METAL3 ;
        RECT 66.67 10.43 68.47 11.43 ;
    END
  END Out_En
END Integration_n_Relu_start

MACRO FakeCellGateDecoder
END FakeCellGateDecoder

MACRO Tgate_swc_fr_Kernel_Horiz_bot_edge
  PIN Q
    DIRECTION INOUT ;
    USE SIGNAL ;
    PORT
      LAYER METAL2 ;
        RECT 30.34 1.93 30.62 2.53 ;
    END
  END Q
  PIN GND
    DIRECTION INOUT ;
    USE SIGNAL ;
    PORT
      LAYER METAL1 ;
        RECT 30.84 21.37 31.64 22.0 ;
    END
  END GND
  PIN Final_row_out
    DIRECTION INOUT ;
    USE SIGNAL ;
    PORT
      LAYER METAL2 ;
        RECT 56.59 2.61 56.93 3.41 ;
    END
  END Final_row_out
  PIN I_m
    DIRECTION INOUT ;
    USE SIGNAL ;
    PORT
      LAYER METAL2 ;
        RECT 56.26 12.7 56.93 13.7 ;
    END
  END I_m
  PIN I_p
    DIRECTION INOUT ;
    USE SIGNAL ;
    PORT
      LAYER METAL2 ;
        RECT 56.26 16.27 56.93 17.27 ;
    END
  END I_p
  PIN Vd<0>
    DIRECTION INOUT ;
    USE SIGNAL ;
    PORT
      LAYER METAL1 ;
        RECT 0.0 17.5 0.42 18.2 ;
    END
  END Vd<0>
  PIN RUN_HV
    DIRECTION INOUT ;
    USE SIGNAL ;
    PORT
      LAYER METAL2 ;
        RECT 23.12 21.33 23.92 22.0 ;
    END
  END RUN_HV
  PIN VINJ
    DIRECTION INOUT ;
    USE SIGNAL ;
    PORT
      LAYER METAL2 ;
        RECT 9.08 21.33 10.08 22.0 ;
    END
  END VINJ
  PIN Vd_prog_0_out
    DIRECTION INOUT ;
    USE SIGNAL ;
    PORT
      LAYER METAL2 ;
        RECT 56.26 18.87 56.93 19.87 ;
    END
  END Vd_prog_0_out
  PIN Din_Glb_in
    DIRECTION INOUT ;
    USE SIGNAL ;
    PORT
      LAYER METAL1 ;
        RECT 54.82 21.4 55.62 22.0 ;
    END
  END Din_Glb_in
  PIN Din_Glb_out
    DIRECTION INOUT ;
    USE SIGNAL ;
    PORT
      LAYER METAL1 ;
        RECT 54.82 0.0 55.62 0.6 ;
    END
  END Din_Glb_out
  PIN Final_rw_out
    DIRECTION INOUT ;
    USE SIGNAL ;
    PORT
      LAYER METAL1 ;
        RECT 52.52 21.4 53.32 22.0 ;
    END
  END Final_rw_out
  PIN Final_rw_in
    DIRECTION INOUT ;
    USE SIGNAL ;
    PORT
      LAYER METAL1 ;
        RECT 52.52 1.88 53.32 2.48 ;
    END
  END Final_rw_in
  PIN Vd_prog_0_in
    DIRECTION INOUT ;
    USE SIGNAL ;
    PORT
      LAYER METAL1 ;
        RECT 0.0 20.3 0.41 20.8 ;
    END
  END Vd_prog_0_in
  PIN Din_int
    DIRECTION INOUT ;
    USE SIGNAL ;
    PORT
      LAYER METAL1 ;
        RECT 49.82 21.6 50.52 22.0 ;
    END
  END Din_int
  PIN DVDD
    DIRECTION INOUT ;
    USE SIGNAL ;
    PORT
      LAYER METAL1 ;
        RECT 43.41 21.37 44.11 22.0 ;
    END
  END DVDD
  PIN RSTB
    DIRECTION INOUT ;
    USE SIGNAL ;
    PORT
      LAYER METAL1 ;
        RECT 40.9 21.37 41.6 22.0 ;
    END
  END RSTB
  PIN CLK
    DIRECTION INOUT ;
    USE SIGNAL ;
    PORT
      LAYER METAL1 ;
        RECT 39.49 21.37 40.19 22.0 ;
    END
  END CLK
  PIN CLKB
    DIRECTION INOUT ;
    USE SIGNAL ;
    PORT
      LAYER METAL1 ;
        RECT 38.26 21.37 38.96 22.0 ;
    END
  END CLKB
  PIN Vd<3>
    DIRECTION INOUT ;
    USE SIGNAL ;
    PORT
      LAYER METAL1 ;
        RECT 0.0 3.3 0.42 4.0 ;
    END
  END Vd<3>
  PIN Vd<2>
    DIRECTION INOUT ;
    USE SIGNAL ;
    PORT
      LAYER METAL1 ;
        RECT 0.0 6.33 0.42 7.03 ;
    END
  END Vd<2>
  PIN Vd<1>
    DIRECTION INOUT ;
    USE SIGNAL ;
    PORT
      LAYER METAL1 ;
        RECT 0.0 14.5 0.42 15.2 ;
    END
  END Vd<1>
END Tgate_swc_fr_Kernel_Horiz_bot_edge

MACRO tile_analog_frame
  PIN n_VTUN
    DIRECTION INOUT ;
    USE SIGNAL ;
    PORT
      LAYER METAL3 ;
        RECT 13.3 2183.21 14.7 2186.01 ;
    END
  END n_VTUN
  PIN n_DVDD
    DIRECTION INOUT ;
    USE SIGNAL ;
    PORT
      LAYER METAL3 ;
        RECT 27.3 2183.21 28.7 2186.01 ;
    END
  END n_DVDD
  PIN n_AVDD
    DIRECTION INOUT ;
    USE SIGNAL ;
    PORT
      LAYER METAL3 ;
        RECT 41.3 2183.21 42.7 2186.01 ;
    END
  END n_AVDD
  PIN n_GND
    DIRECTION INOUT ;
    USE SIGNAL ;
    PORT
      LAYER METAL3 ;
        RECT 55.3 2183.21 56.7 2186.01 ;
    END
  END n_GND
  PIN n_VINJ
    DIRECTION INOUT ;
    USE SIGNAL ;
    PORT
      LAYER METAL3 ;
        RECT 69.3 2183.21 70.7 2186.01 ;
    END
  END n_VINJ
  PIN n_VGPROG
    DIRECTION INOUT ;
    USE SIGNAL ;
    PORT
      LAYER METAL3 ;
        RECT 83.3 2183.21 84.7 2186.01 ;
    END
  END n_VGPROG
  PIN n_prog_hv
    DIRECTION INOUT ;
    USE SIGNAL ;
    PORT
      LAYER METAL3 ;
        RECT 97.3 2183.21 98.7 2186.01 ;
    END
  END n_prog_hv
  PIN n_run_hv
    DIRECTION INOUT ;
    USE SIGNAL ;
    PORT
      LAYER METAL3 ;
        RECT 111.3 2183.21 112.7 2186.01 ;
    END
  END n_run_hv
  PIN n_Global_rst_b
    DIRECTION INOUT ;
    USE SIGNAL ;
    PORT
      LAYER METAL3 ;
        RECT 125.3 2183.21 126.7 2186.01 ;
    END
  END n_Global_rst_b
  PIN n_AVDD_by_2
    DIRECTION INOUT ;
    USE SIGNAL ;
    PORT
      LAYER METAL3 ;
        RECT 139.3 2183.21 140.7 2186.01 ;
    END
  END n_AVDD_by_2
  PIN n_CNN_G_bit<0>
    DIRECTION INOUT ;
    USE SIGNAL ;
    PORT
      LAYER METAL3 ;
        RECT 153.3 2183.21 154.7 2186.01 ;
    END
  END n_CNN_G_bit<0>
  PIN n_CNN_G_bit<1>
    DIRECTION INOUT ;
    USE SIGNAL ;
    PORT
      LAYER METAL3 ;
        RECT 167.3 2183.21 168.7 2186.01 ;
    END
  END n_CNN_G_bit<1>
  PIN n_CNN_G_bit<2>
    DIRECTION INOUT ;
    USE SIGNAL ;
    PORT
      LAYER METAL3 ;
        RECT 181.3 2183.21 182.7 2186.01 ;
    END
  END n_CNN_G_bit<2>
  PIN n_CNN_G_bit<3>
    DIRECTION INOUT ;
    USE SIGNAL ;
    PORT
      LAYER METAL3 ;
        RECT 195.3 2183.21 196.7 2186.01 ;
    END
  END n_CNN_G_bit<3>
  PIN n_CNN_G_bit<4>
    DIRECTION INOUT ;
    USE SIGNAL ;
    PORT
      LAYER METAL3 ;
        RECT 209.3 2183.21 210.7 2186.01 ;
    END
  END n_CNN_G_bit<4>
  PIN n_CNN_G_bit<5>
    DIRECTION INOUT ;
    USE SIGNAL ;
    PORT
      LAYER METAL3 ;
        RECT 223.3 2183.21 224.7 2186.01 ;
    END
  END n_CNN_G_bit<5>
  PIN n_CNN_G_bit<6>
    DIRECTION INOUT ;
    USE SIGNAL ;
    PORT
      LAYER METAL3 ;
        RECT 237.3 2183.21 238.7 2186.01 ;
    END
  END n_CNN_G_bit<6>
  PIN n_CNN_Dr_bit<0>
    DIRECTION INOUT ;
    USE SIGNAL ;
    PORT
      LAYER METAL3 ;
        RECT 251.3 2183.21 252.7 2186.01 ;
    END
  END n_CNN_Dr_bit<0>
  PIN n_CNN_Dr_bit<1>
    DIRECTION INOUT ;
    USE SIGNAL ;
    PORT
      LAYER METAL3 ;
        RECT 265.3 2183.21 266.7 2186.01 ;
    END
  END n_CNN_Dr_bit<1>
  PIN n_CNN_Dr_bit<2>
    DIRECTION INOUT ;
    USE SIGNAL ;
    PORT
      LAYER METAL3 ;
        RECT 279.3 2183.21 280.7 2186.01 ;
    END
  END n_CNN_Dr_bit<2>
  PIN n_CNN_Dr_bit<3>
    DIRECTION INOUT ;
    USE SIGNAL ;
    PORT
      LAYER METAL3 ;
        RECT 293.3 2183.21 294.7 2186.01 ;
    END
  END n_CNN_Dr_bit<3>
  PIN n_CNN_Dr_bit<4>
    DIRECTION INOUT ;
    USE SIGNAL ;
    PORT
      LAYER METAL3 ;
        RECT 307.3 2183.21 308.7 2186.01 ;
    END
  END n_CNN_Dr_bit<4>
  PIN n_CNN_Dr_bit<5>
    DIRECTION INOUT ;
    USE SIGNAL ;
    PORT
      LAYER METAL3 ;
        RECT 321.3 2183.21 322.7 2186.01 ;
    END
  END n_CNN_Dr_bit<5>
  PIN n_CNN_Dr_bit<6>
    DIRECTION INOUT ;
    USE SIGNAL ;
    PORT
      LAYER METAL3 ;
        RECT 335.3 2183.21 336.7 2186.01 ;
    END
  END n_CNN_Dr_bit<6>
  PIN n_CNN_Dr_bit<7>
    DIRECTION INOUT ;
    USE SIGNAL ;
    PORT
      LAYER METAL3 ;
        RECT 349.3 2183.21 350.7 2186.01 ;
    END
  END n_CNN_Dr_bit<7>
  PIN n_Prog_Drainline
    DIRECTION INOUT ;
    USE SIGNAL ;
    PORT
      LAYER METAL3 ;
        RECT 363.3 2183.21 364.7 2186.01 ;
    END
  END n_Prog_Drainline
  PIN n_Run_Drainline
    DIRECTION INOUT ;
    USE SIGNAL ;
    PORT
      LAYER METAL3 ;
        RECT 377.3 2183.21 378.7 2186.01 ;
    END
  END n_Run_Drainline
  PIN n_CNN_ly0_G_En
    DIRECTION INOUT ;
    USE SIGNAL ;
    PORT
      LAYER METAL3 ;
        RECT 391.3 2183.21 392.7 2186.01 ;
    END
  END n_CNN_ly0_G_En
  PIN n_CNN_ly0_AP_G_En
    DIRECTION INOUT ;
    USE SIGNAL ;
    PORT
      LAYER METAL3 ;
        RECT 405.3 2183.21 406.7 2186.01 ;
    END
  END n_CNN_ly0_AP_G_En
  PIN n_CNN_ly0_Dr_En
    DIRECTION INOUT ;
    USE SIGNAL ;
    PORT
      LAYER METAL3 ;
        RECT 419.3 2183.21 420.7 2186.01 ;
    END
  END n_CNN_ly0_Dr_En
  PIN n_CNN_ly0_k_col_Din
    DIRECTION INOUT ;
    USE SIGNAL ;
    PORT
      LAYER METAL3 ;
        RECT 433.3 2183.21 434.7 2186.01 ;
    END
  END n_CNN_ly0_k_col_Din
  PIN n_CNN_ly0_k_col_CLKB
    DIRECTION INOUT ;
    USE SIGNAL ;
    PORT
      LAYER METAL3 ;
        RECT 447.3 2183.21 448.7 2186.01 ;
    END
  END n_CNN_ly0_k_col_CLKB
  PIN n_CNN_ly0_k_col_RST_B
    DIRECTION INOUT ;
    USE SIGNAL ;
    PORT
      LAYER METAL3 ;
        RECT 461.3 2183.21 462.7 2186.01 ;
    END
  END n_CNN_ly0_k_col_RST_B
  PIN n_CNN_ly0_k_col_CLK
    DIRECTION INOUT ;
    USE SIGNAL ;
    PORT
      LAYER METAL3 ;
        RECT 475.3 2183.21 476.7 2186.01 ;
    END
  END n_CNN_ly0_k_col_CLK
  PIN n_CNN_ly0_Vinp<0>
    DIRECTION INOUT ;
    USE SIGNAL ;
    PORT
      LAYER METAL3 ;
        RECT 489.3 2183.21 490.7 2186.01 ;
    END
  END n_CNN_ly0_Vinp<0>
  PIN n_CNN_ly0_Vinp<1>
    DIRECTION INOUT ;
    USE SIGNAL ;
    PORT
      LAYER METAL3 ;
        RECT 503.3 2183.21 504.7 2186.01 ;
    END
  END n_CNN_ly0_Vinp<1>
  PIN n_CNN_ly0_Vinp<2>
    DIRECTION INOUT ;
    USE SIGNAL ;
    PORT
      LAYER METAL3 ;
        RECT 517.3 2183.21 518.7 2186.01 ;
    END
  END n_CNN_ly0_Vinp<2>
  PIN n_CNN_ly0_Intg_Din
    DIRECTION INOUT ;
    USE SIGNAL ;
    PORT
      LAYER METAL3 ;
        RECT 531.3 2183.21 532.7 2186.01 ;
    END
  END n_CNN_ly0_Intg_Din
  PIN n_CNN_ly0_Intg_CLKB
    DIRECTION INOUT ;
    USE SIGNAL ;
    PORT
      LAYER METAL3 ;
        RECT 545.3 2183.21 546.7 2186.01 ;
    END
  END n_CNN_ly0_Intg_CLKB
  PIN n_CNN_ly0_Intg_RST_B
    DIRECTION INOUT ;
    USE SIGNAL ;
    PORT
      LAYER METAL3 ;
        RECT 559.3 2183.21 560.7 2186.01 ;
    END
  END n_CNN_ly0_Intg_RST_B
  PIN n_CNN_ly0_Intg_CLK
    DIRECTION INOUT ;
    USE SIGNAL ;
    PORT
      LAYER METAL3 ;
        RECT 573.3 2183.21 574.7 2186.01 ;
    END
  END n_CNN_ly0_Intg_CLK
  PIN n_CNN_ly0_k_rw_Din
    DIRECTION INOUT ;
    USE SIGNAL ;
    PORT
      LAYER METAL3 ;
        RECT 587.3 2183.21 588.7 2186.01 ;
    END
  END n_CNN_ly0_k_rw_Din
  PIN n_CNN_ly0_k_rw_CLKB
    DIRECTION INOUT ;
    USE SIGNAL ;
    PORT
      LAYER METAL3 ;
        RECT 601.3 2183.21 602.7 2186.01 ;
    END
  END n_CNN_ly0_k_rw_CLKB
  PIN n_CNN_ly0_k_rw_RST_B
    DIRECTION INOUT ;
    USE SIGNAL ;
    PORT
      LAYER METAL3 ;
        RECT 615.3 2183.21 616.7 2186.01 ;
    END
  END n_CNN_ly0_k_rw_RST_B
  PIN n_CNN_ly0_k_rw_CLK
    DIRECTION INOUT ;
    USE SIGNAL ;
    PORT
      LAYER METAL3 ;
        RECT 629.3 2183.21 630.7 2186.01 ;
    END
  END n_CNN_ly0_k_rw_CLK
  PIN n_CNN_ly0_AP_Relu_Vb
    DIRECTION INOUT ;
    USE SIGNAL ;
    PORT
      LAYER METAL3 ;
        RECT 643.3 2183.21 644.7 2186.01 ;
    END
  END n_CNN_ly0_AP_Relu_Vb
  PIN n_CNN_ly1_G_En
    DIRECTION INOUT ;
    USE SIGNAL ;
    PORT
      LAYER METAL3 ;
        RECT 657.3 2183.21 658.7 2186.01 ;
    END
  END n_CNN_ly1_G_En
  PIN n_CNN_ly1_Dr_En
    DIRECTION INOUT ;
    USE SIGNAL ;
    PORT
      LAYER METAL3 ;
        RECT 671.3 2183.21 672.7 2186.01 ;
    END
  END n_CNN_ly1_Dr_En
  PIN n_CNN_ly1_k_col_Din
    DIRECTION INOUT ;
    USE SIGNAL ;
    PORT
      LAYER METAL3 ;
        RECT 685.3 2183.21 686.7 2186.01 ;
    END
  END n_CNN_ly1_k_col_Din
  PIN n_CNN_ly1_k_col_CLKB
    DIRECTION INOUT ;
    USE SIGNAL ;
    PORT
      LAYER METAL3 ;
        RECT 699.3 2183.21 700.7 2186.01 ;
    END
  END n_CNN_ly1_k_col_CLKB
  PIN n_CNN_ly1_k_col_RST_B
    DIRECTION INOUT ;
    USE SIGNAL ;
    PORT
      LAYER METAL3 ;
        RECT 713.3 2183.21 714.7 2186.01 ;
    END
  END n_CNN_ly1_k_col_RST_B
  PIN n_CNN_ly1_k_col_CLK
    DIRECTION INOUT ;
    USE SIGNAL ;
    PORT
      LAYER METAL3 ;
        RECT 727.3 2183.21 728.7 2186.01 ;
    END
  END n_CNN_ly1_k_col_CLK
  PIN n_CNN_ly1_Intg_Din
    DIRECTION INOUT ;
    USE SIGNAL ;
    PORT
      LAYER METAL3 ;
        RECT 741.3 2183.21 742.7 2186.01 ;
    END
  END n_CNN_ly1_Intg_Din
  PIN n_CNN_ly1_Intg_CLKB
    DIRECTION INOUT ;
    USE SIGNAL ;
    PORT
      LAYER METAL3 ;
        RECT 755.3 2183.21 756.7 2186.01 ;
    END
  END n_CNN_ly1_Intg_CLKB
  PIN n_CNN_ly1_Intg_RST_B
    DIRECTION INOUT ;
    USE SIGNAL ;
    PORT
      LAYER METAL3 ;
        RECT 769.3 2183.21 770.7 2186.01 ;
    END
  END n_CNN_ly1_Intg_RST_B
  PIN n_CNN_ly1_Intg_CLK
    DIRECTION INOUT ;
    USE SIGNAL ;
    PORT
      LAYER METAL3 ;
        RECT 783.3 2183.21 784.7 2186.01 ;
    END
  END n_CNN_ly1_Intg_CLK
  PIN n_CNN_ly1_k_rw_Din
    DIRECTION INOUT ;
    USE SIGNAL ;
    PORT
      LAYER METAL3 ;
        RECT 797.3 2183.21 798.7 2186.01 ;
    END
  END n_CNN_ly1_k_rw_Din
  PIN n_CNN_ly1_k_rw_CLKB
    DIRECTION INOUT ;
    USE SIGNAL ;
    PORT
      LAYER METAL3 ;
        RECT 811.3 2183.21 812.7 2186.01 ;
    END
  END n_CNN_ly1_k_rw_CLKB
  PIN n_CNN_ly1_k_rw_RST_B
    DIRECTION INOUT ;
    USE SIGNAL ;
    PORT
      LAYER METAL3 ;
        RECT 825.3 2183.21 826.7 2186.01 ;
    END
  END n_CNN_ly1_k_rw_RST_B
  PIN n_CNN_ly1_k_rw_CLK
    DIRECTION INOUT ;
    USE SIGNAL ;
    PORT
      LAYER METAL3 ;
        RECT 839.3 2183.21 840.7 2186.01 ;
    END
  END n_CNN_ly1_k_rw_CLK
  PIN n_sample_buf_Vb
    DIRECTION INOUT ;
    USE SIGNAL ;
    PORT
      LAYER METAL3 ;
        RECT 853.3 2183.21 854.7 2186.01 ;
    END
  END n_sample_buf_Vb
  PIN n_Relu_Vb
    DIRECTION INOUT ;
    USE SIGNAL ;
    PORT
      LAYER METAL3 ;
        RECT 867.3 2183.21 868.7 2186.01 ;
    END
  END n_Relu_Vb
  PIN s_CNN_ly1_Out<0>
    DIRECTION INOUT ;
    USE SIGNAL ;
    PORT
      LAYER METAL3 ;
        RECT 13.3 0.0 14.7 2.8 ;
    END
  END s_CNN_ly1_Out<0>
  PIN s_CNN_ly1_Out<1>
    DIRECTION INOUT ;
    USE SIGNAL ;
    PORT
      LAYER METAL3 ;
        RECT 27.3 0.0 28.7 2.8 ;
    END
  END s_CNN_ly1_Out<1>
  PIN s_CNN_ly1_Out<2>
    DIRECTION INOUT ;
    USE SIGNAL ;
    PORT
      LAYER METAL3 ;
        RECT 41.3 0.0 42.7 2.8 ;
    END
  END s_CNN_ly1_Out<2>
  PIN s_CNN_ly1_Out<3>
    DIRECTION INOUT ;
    USE SIGNAL ;
    PORT
      LAYER METAL3 ;
        RECT 55.3 0.0 56.7 2.8 ;
    END
  END s_CNN_ly1_Out<3>
  PIN s_CNN_ly1_Out<4>
    DIRECTION INOUT ;
    USE SIGNAL ;
    PORT
      LAYER METAL3 ;
        RECT 69.3 0.0 70.7 2.8 ;
    END
  END s_CNN_ly1_Out<4>
  PIN s_CNN_ly1_Out<5>
    DIRECTION INOUT ;
    USE SIGNAL ;
    PORT
      LAYER METAL3 ;
        RECT 83.3 0.0 84.7 2.8 ;
    END
  END s_CNN_ly1_Out<5>
  PIN s_CNN_ly1_Out<6>
    DIRECTION INOUT ;
    USE SIGNAL ;
    PORT
      LAYER METAL3 ;
        RECT 97.3 0.0 98.7 2.8 ;
    END
  END s_CNN_ly1_Out<6>
  PIN s_CNN_ly1_Out<7>
    DIRECTION INOUT ;
    USE SIGNAL ;
    PORT
      LAYER METAL3 ;
        RECT 111.3 0.0 112.7 2.8 ;
    END
  END s_CNN_ly1_Out<7>
  PIN s_CNN_ly1_Out<8>
    DIRECTION INOUT ;
    USE SIGNAL ;
    PORT
      LAYER METAL3 ;
        RECT 125.3 0.0 126.7 2.8 ;
    END
  END s_CNN_ly1_Out<8>
  PIN s_CNN_ly1_Out<9>
    DIRECTION INOUT ;
    USE SIGNAL ;
    PORT
      LAYER METAL3 ;
        RECT 139.3 0.0 140.7 2.8 ;
    END
  END s_CNN_ly1_Out<9>
  PIN s_CNN_ly1_Out<10>
    DIRECTION INOUT ;
    USE SIGNAL ;
    PORT
      LAYER METAL3 ;
        RECT 153.3 0.0 154.7 2.8 ;
    END
  END s_CNN_ly1_Out<10>
  PIN s_CNN_ly1_Out<11>
    DIRECTION INOUT ;
    USE SIGNAL ;
    PORT
      LAYER METAL3 ;
        RECT 167.3 0.0 168.7 2.8 ;
    END
  END s_CNN_ly1_Out<11>
  PIN s_CNN_ly1_Out<12>
    DIRECTION INOUT ;
    USE SIGNAL ;
    PORT
      LAYER METAL3 ;
        RECT 181.3 0.0 182.7 2.8 ;
    END
  END s_CNN_ly1_Out<12>
  PIN s_CNN_ly1_Out<13>
    DIRECTION INOUT ;
    USE SIGNAL ;
    PORT
      LAYER METAL3 ;
        RECT 195.3 0.0 196.7 2.8 ;
    END
  END s_CNN_ly1_Out<13>
  PIN s_CNN_ly1_Out<14>
    DIRECTION INOUT ;
    USE SIGNAL ;
    PORT
      LAYER METAL3 ;
        RECT 209.3 0.0 210.7 2.8 ;
    END
  END s_CNN_ly1_Out<14>
  PIN s_CNN_ly1_Out<15>
    DIRECTION INOUT ;
    USE SIGNAL ;
    PORT
      LAYER METAL3 ;
        RECT 223.3 0.0 224.7 2.8 ;
    END
  END s_CNN_ly1_Out<15>
  PIN s_CNN_ly1_Out<16>
    DIRECTION INOUT ;
    USE SIGNAL ;
    PORT
      LAYER METAL3 ;
        RECT 237.3 0.0 238.7 2.8 ;
    END
  END s_CNN_ly1_Out<16>
  PIN s_CNN_ly1_Out<17>
    DIRECTION INOUT ;
    USE SIGNAL ;
    PORT
      LAYER METAL3 ;
        RECT 251.3 0.0 252.7 2.8 ;
    END
  END s_CNN_ly1_Out<17>
  PIN s_CNN_ly1_Out<18>
    DIRECTION INOUT ;
    USE SIGNAL ;
    PORT
      LAYER METAL3 ;
        RECT 265.3 0.0 266.7 2.8 ;
    END
  END s_CNN_ly1_Out<18>
  PIN s_CNN_ly1_Out<19>
    DIRECTION INOUT ;
    USE SIGNAL ;
    PORT
      LAYER METAL3 ;
        RECT 279.3 0.0 280.7 2.8 ;
    END
  END s_CNN_ly1_Out<19>
  PIN s_CNN_ly1_Out<20>
    DIRECTION INOUT ;
    USE SIGNAL ;
    PORT
      LAYER METAL3 ;
        RECT 293.3 0.0 294.7 2.8 ;
    END
  END s_CNN_ly1_Out<20>
  PIN s_CNN_ly1_Out<21>
    DIRECTION INOUT ;
    USE SIGNAL ;
    PORT
      LAYER METAL3 ;
        RECT 307.3 0.0 308.7 2.8 ;
    END
  END s_CNN_ly1_Out<21>
  PIN s_CNN_ly1_Out<22>
    DIRECTION INOUT ;
    USE SIGNAL ;
    PORT
      LAYER METAL3 ;
        RECT 321.3 0.0 322.7 2.8 ;
    END
  END s_CNN_ly1_Out<22>
  PIN s_CNN_ly1_Out<23>
    DIRECTION INOUT ;
    USE SIGNAL ;
    PORT
      LAYER METAL3 ;
        RECT 335.3 0.0 336.7 2.8 ;
    END
  END s_CNN_ly1_Out<23>
  PIN s_CNN_ly1_Out<24>
    DIRECTION INOUT ;
    USE SIGNAL ;
    PORT
      LAYER METAL3 ;
        RECT 349.3 0.0 350.7 2.8 ;
    END
  END s_CNN_ly1_Out<24>
  PIN s_CNN_ly1_Out<25>
    DIRECTION INOUT ;
    USE SIGNAL ;
    PORT
      LAYER METAL3 ;
        RECT 363.3 0.0 364.7 2.8 ;
    END
  END s_CNN_ly1_Out<25>
  PIN s_CNN_ly1_Out<26>
    DIRECTION INOUT ;
    USE SIGNAL ;
    PORT
      LAYER METAL3 ;
        RECT 377.3 0.0 378.7 2.8 ;
    END
  END s_CNN_ly1_Out<26>
  PIN s_CNN_ly1_Out<27>
    DIRECTION INOUT ;
    USE SIGNAL ;
    PORT
      LAYER METAL3 ;
        RECT 391.3 0.0 392.7 2.8 ;
    END
  END s_CNN_ly1_Out<27>
  PIN s_CNN_ly1_Out<28>
    DIRECTION INOUT ;
    USE SIGNAL ;
    PORT
      LAYER METAL3 ;
        RECT 405.3 0.0 406.7 2.8 ;
    END
  END s_CNN_ly1_Out<28>
  PIN s_CNN_ly1_Out<29>
    DIRECTION INOUT ;
    USE SIGNAL ;
    PORT
      LAYER METAL3 ;
        RECT 419.3 0.0 420.7 2.8 ;
    END
  END s_CNN_ly1_Out<29>
  PIN s_CNN_ly1_Out<30>
    DIRECTION INOUT ;
    USE SIGNAL ;
    PORT
      LAYER METAL3 ;
        RECT 433.3 0.0 434.7 2.8 ;
    END
  END s_CNN_ly1_Out<30>
  PIN s_CNN_ly1_Out<31>
    DIRECTION INOUT ;
    USE SIGNAL ;
    PORT
      LAYER METAL3 ;
        RECT 447.3 0.0 448.7 2.8 ;
    END
  END s_CNN_ly1_Out<31>
  PIN s_CNN_ly1_Out<32>
    DIRECTION INOUT ;
    USE SIGNAL ;
    PORT
      LAYER METAL3 ;
        RECT 461.3 0.0 462.7 2.8 ;
    END
  END s_CNN_ly1_Out<32>
  PIN s_CNN_ly1_Out<33>
    DIRECTION INOUT ;
    USE SIGNAL ;
    PORT
      LAYER METAL3 ;
        RECT 475.3 0.0 476.7 2.8 ;
    END
  END s_CNN_ly1_Out<33>
  PIN s_CNN_ly1_Out<34>
    DIRECTION INOUT ;
    USE SIGNAL ;
    PORT
      LAYER METAL3 ;
        RECT 489.3 0.0 490.7 2.8 ;
    END
  END s_CNN_ly1_Out<34>
  PIN s_CNN_ly1_Out<35>
    DIRECTION INOUT ;
    USE SIGNAL ;
    PORT
      LAYER METAL3 ;
        RECT 503.3 0.0 504.7 2.8 ;
    END
  END s_CNN_ly1_Out<35>
  PIN s_CNN_ly1_Out<36>
    DIRECTION INOUT ;
    USE SIGNAL ;
    PORT
      LAYER METAL3 ;
        RECT 517.3 0.0 518.7 2.8 ;
    END
  END s_CNN_ly1_Out<36>
  PIN s_CNN_ly1_Out<37>
    DIRECTION INOUT ;
    USE SIGNAL ;
    PORT
      LAYER METAL3 ;
        RECT 531.3 0.0 532.7 2.8 ;
    END
  END s_CNN_ly1_Out<37>
  PIN s_CNN_ly1_Out<38>
    DIRECTION INOUT ;
    USE SIGNAL ;
    PORT
      LAYER METAL3 ;
        RECT 545.3 0.0 546.7 2.8 ;
    END
  END s_CNN_ly1_Out<38>
  PIN s_CNN_ly1_Out<39>
    DIRECTION INOUT ;
    USE SIGNAL ;
    PORT
      LAYER METAL3 ;
        RECT 559.3 0.0 560.7 2.8 ;
    END
  END s_CNN_ly1_Out<39>
  PIN s_CNN_ly1_Out<40>
    DIRECTION INOUT ;
    USE SIGNAL ;
    PORT
      LAYER METAL3 ;
        RECT 573.3 0.0 574.7 2.8 ;
    END
  END s_CNN_ly1_Out<40>
  PIN s_CNN_ly1_Out<41>
    DIRECTION INOUT ;
    USE SIGNAL ;
    PORT
      LAYER METAL3 ;
        RECT 587.3 0.0 588.7 2.8 ;
    END
  END s_CNN_ly1_Out<41>
  PIN s_CNN_ly1_Out<42>
    DIRECTION INOUT ;
    USE SIGNAL ;
    PORT
      LAYER METAL3 ;
        RECT 601.3 0.0 602.7 2.8 ;
    END
  END s_CNN_ly1_Out<42>
  PIN s_CNN_ly1_Out<43>
    DIRECTION INOUT ;
    USE SIGNAL ;
    PORT
      LAYER METAL3 ;
        RECT 615.3 0.0 616.7 2.8 ;
    END
  END s_CNN_ly1_Out<43>
  PIN s_CNN_ly1_Out<44>
    DIRECTION INOUT ;
    USE SIGNAL ;
    PORT
      LAYER METAL3 ;
        RECT 629.3 0.0 630.7 2.8 ;
    END
  END s_CNN_ly1_Out<44>
  PIN s_CNN_ly1_Out<45>
    DIRECTION INOUT ;
    USE SIGNAL ;
    PORT
      LAYER METAL3 ;
        RECT 643.3 0.0 644.7 2.8 ;
    END
  END s_CNN_ly1_Out<45>
  PIN s_CNN_ly1_Out<46>
    DIRECTION INOUT ;
    USE SIGNAL ;
    PORT
      LAYER METAL3 ;
        RECT 657.3 0.0 658.7 2.8 ;
    END
  END s_CNN_ly1_Out<46>
  PIN s_CNN_ly1_Out<47>
    DIRECTION INOUT ;
    USE SIGNAL ;
    PORT
      LAYER METAL3 ;
        RECT 671.3 0.0 672.7 2.8 ;
    END
  END s_CNN_ly1_Out<47>
  PIN s_CNN_ly1_Out<48>
    DIRECTION INOUT ;
    USE SIGNAL ;
    PORT
      LAYER METAL3 ;
        RECT 685.3 0.0 686.7 2.8 ;
    END
  END s_CNN_ly1_Out<48>
  PIN s_CNN_ly1_Out<49>
    DIRECTION INOUT ;
    USE SIGNAL ;
    PORT
      LAYER METAL3 ;
        RECT 699.3 0.0 700.7 2.8 ;
    END
  END s_CNN_ly1_Out<49>
  PIN s_CNN_ly1_Out<50>
    DIRECTION INOUT ;
    USE SIGNAL ;
    PORT
      LAYER METAL3 ;
        RECT 713.3 0.0 714.7 2.8 ;
    END
  END s_CNN_ly1_Out<50>
  PIN s_CNN_ly1_Out<51>
    DIRECTION INOUT ;
    USE SIGNAL ;
    PORT
      LAYER METAL3 ;
        RECT 727.3 0.0 728.7 2.8 ;
    END
  END s_CNN_ly1_Out<51>
  PIN s_CNN_ly1_Out<52>
    DIRECTION INOUT ;
    USE SIGNAL ;
    PORT
      LAYER METAL3 ;
        RECT 741.3 0.0 742.7 2.8 ;
    END
  END s_CNN_ly1_Out<52>
  PIN s_CNN_ly1_Out<53>
    DIRECTION INOUT ;
    USE SIGNAL ;
    PORT
      LAYER METAL3 ;
        RECT 755.3 0.0 756.7 2.8 ;
    END
  END s_CNN_ly1_Out<53>
  PIN s_CNN_ly1_Out<54>
    DIRECTION INOUT ;
    USE SIGNAL ;
    PORT
      LAYER METAL3 ;
        RECT 769.3 0.0 770.7 2.8 ;
    END
  END s_CNN_ly1_Out<54>
  PIN s_CNN_ly1_Out<55>
    DIRECTION INOUT ;
    USE SIGNAL ;
    PORT
      LAYER METAL3 ;
        RECT 783.3 0.0 784.7 2.8 ;
    END
  END s_CNN_ly1_Out<55>
  PIN s_CNN_ly1_Out<56>
    DIRECTION INOUT ;
    USE SIGNAL ;
    PORT
      LAYER METAL3 ;
        RECT 797.3 0.0 798.7 2.8 ;
    END
  END s_CNN_ly1_Out<56>
  PIN s_CNN_ly1_Out<57>
    DIRECTION INOUT ;
    USE SIGNAL ;
    PORT
      LAYER METAL3 ;
        RECT 811.3 0.0 812.7 2.8 ;
    END
  END s_CNN_ly1_Out<57>
  PIN s_CNN_ly1_Out<58>
    DIRECTION INOUT ;
    USE SIGNAL ;
    PORT
      LAYER METAL3 ;
        RECT 825.3 0.0 826.7 2.8 ;
    END
  END s_CNN_ly1_Out<58>
  PIN s_CNN_ly1_Out<59>
    DIRECTION INOUT ;
    USE SIGNAL ;
    PORT
      LAYER METAL3 ;
        RECT 839.3 0.0 840.7 2.8 ;
    END
  END s_CNN_ly1_Out<59>
  PIN s_CNN_ly1_Out<60>
    DIRECTION INOUT ;
    USE SIGNAL ;
    PORT
      LAYER METAL3 ;
        RECT 853.3 0.0 854.7 2.8 ;
    END
  END s_CNN_ly1_Out<60>
  PIN s_CNN_ly1_Out<61>
    DIRECTION INOUT ;
    USE SIGNAL ;
    PORT
      LAYER METAL3 ;
        RECT 867.3 0.0 868.7 2.8 ;
    END
  END s_CNN_ly1_Out<61>
  PIN s_CNN_ly1_Out<62>
    DIRECTION INOUT ;
    USE SIGNAL ;
    PORT
      LAYER METAL3 ;
        RECT 881.3 0.0 882.7 2.8 ;
    END
  END s_CNN_ly1_Out<62>
  PIN s_CNN_ly1_Out<63>
    DIRECTION INOUT ;
    USE SIGNAL ;
    PORT
      LAYER METAL3 ;
        RECT 895.3 0.0 896.7 2.8 ;
    END
  END s_CNN_ly1_Out<63>
  PIN s_CNN_ly1_Out<64>
    DIRECTION INOUT ;
    USE SIGNAL ;
    PORT
      LAYER METAL3 ;
        RECT 909.3 0.0 910.7 2.8 ;
    END
  END s_CNN_ly1_Out<64>
  PIN s_CNN_ly1_Out<65>
    DIRECTION INOUT ;
    USE SIGNAL ;
    PORT
      LAYER METAL3 ;
        RECT 923.3 0.0 924.7 2.8 ;
    END
  END s_CNN_ly1_Out<65>
  PIN s_CNN_ly1_Out<66>
    DIRECTION INOUT ;
    USE SIGNAL ;
    PORT
      LAYER METAL3 ;
        RECT 937.3 0.0 938.7 2.8 ;
    END
  END s_CNN_ly1_Out<66>
  PIN s_CNN_ly1_Out<67>
    DIRECTION INOUT ;
    USE SIGNAL ;
    PORT
      LAYER METAL3 ;
        RECT 951.3 0.0 952.7 2.8 ;
    END
  END s_CNN_ly1_Out<67>
  PIN s_CNN_ly1_Out<68>
    DIRECTION INOUT ;
    USE SIGNAL ;
    PORT
      LAYER METAL3 ;
        RECT 965.3 0.0 966.7 2.8 ;
    END
  END s_CNN_ly1_Out<68>
  PIN s_CNN_ly1_Out<69>
    DIRECTION INOUT ;
    USE SIGNAL ;
    PORT
      LAYER METAL3 ;
        RECT 979.3 0.0 980.7 2.8 ;
    END
  END s_CNN_ly1_Out<69>
  PIN s_CNN_ly1_Out<70>
    DIRECTION INOUT ;
    USE SIGNAL ;
    PORT
      LAYER METAL3 ;
        RECT 993.3 0.0 994.7 2.8 ;
    END
  END s_CNN_ly1_Out<70>
  PIN s_CNN_ly1_Out<71>
    DIRECTION INOUT ;
    USE SIGNAL ;
    PORT
      LAYER METAL3 ;
        RECT 1007.3 0.0 1008.7 2.8 ;
    END
  END s_CNN_ly1_Out<71>
  PIN s_CNN_ly1_Out<72>
    DIRECTION INOUT ;
    USE SIGNAL ;
    PORT
      LAYER METAL3 ;
        RECT 1021.3 0.0 1022.7 2.8 ;
    END
  END s_CNN_ly1_Out<72>
  PIN s_CNN_ly1_Out<73>
    DIRECTION INOUT ;
    USE SIGNAL ;
    PORT
      LAYER METAL3 ;
        RECT 1035.3 0.0 1036.7 2.8 ;
    END
  END s_CNN_ly1_Out<73>
  PIN s_CNN_ly1_Out<74>
    DIRECTION INOUT ;
    USE SIGNAL ;
    PORT
      LAYER METAL3 ;
        RECT 1049.3 0.0 1050.7 2.8 ;
    END
  END s_CNN_ly1_Out<74>
  PIN s_CNN_ly1_Out<75>
    DIRECTION INOUT ;
    USE SIGNAL ;
    PORT
      LAYER METAL3 ;
        RECT 1063.3 0.0 1064.7 2.8 ;
    END
  END s_CNN_ly1_Out<75>
  PIN s_CNN_ly1_Out<76>
    DIRECTION INOUT ;
    USE SIGNAL ;
    PORT
      LAYER METAL3 ;
        RECT 1077.3 0.0 1078.7 2.8 ;
    END
  END s_CNN_ly1_Out<76>
  PIN s_CNN_ly1_Out<77>
    DIRECTION INOUT ;
    USE SIGNAL ;
    PORT
      LAYER METAL3 ;
        RECT 1091.3 0.0 1092.7 2.8 ;
    END
  END s_CNN_ly1_Out<77>
  PIN s_CNN_ly1_Out<78>
    DIRECTION INOUT ;
    USE SIGNAL ;
    PORT
      LAYER METAL3 ;
        RECT 1105.3 0.0 1106.7 2.8 ;
    END
  END s_CNN_ly1_Out<78>
  PIN s_CNN_ly1_Out<79>
    DIRECTION INOUT ;
    USE SIGNAL ;
    PORT
      LAYER METAL3 ;
        RECT 1119.3 0.0 1120.7 2.8 ;
    END
  END s_CNN_ly1_Out<79>
  PIN s_CNN_ly1_Out<80>
    DIRECTION INOUT ;
    USE SIGNAL ;
    PORT
      LAYER METAL3 ;
        RECT 1133.3 0.0 1134.7 2.8 ;
    END
  END s_CNN_ly1_Out<80>
  PIN s_CNN_ly1_Out<81>
    DIRECTION INOUT ;
    USE SIGNAL ;
    PORT
      LAYER METAL3 ;
        RECT 1147.3 0.0 1148.7 2.8 ;
    END
  END s_CNN_ly1_Out<81>
  PIN s_CNN_ly1_Out<82>
    DIRECTION INOUT ;
    USE SIGNAL ;
    PORT
      LAYER METAL3 ;
        RECT 1161.3 0.0 1162.7 2.8 ;
    END
  END s_CNN_ly1_Out<82>
  PIN s_CNN_ly1_Out<83>
    DIRECTION INOUT ;
    USE SIGNAL ;
    PORT
      LAYER METAL3 ;
        RECT 1175.3 0.0 1176.7 2.8 ;
    END
  END s_CNN_ly1_Out<83>
  PIN s_CNN_ly1_Out<84>
    DIRECTION INOUT ;
    USE SIGNAL ;
    PORT
      LAYER METAL3 ;
        RECT 1189.3 0.0 1190.7 2.8 ;
    END
  END s_CNN_ly1_Out<84>
  PIN s_CNN_ly1_Out<85>
    DIRECTION INOUT ;
    USE SIGNAL ;
    PORT
      LAYER METAL3 ;
        RECT 1203.3 0.0 1204.7 2.8 ;
    END
  END s_CNN_ly1_Out<85>
  PIN s_CNN_ly1_Out<86>
    DIRECTION INOUT ;
    USE SIGNAL ;
    PORT
      LAYER METAL3 ;
        RECT 1217.3 0.0 1218.7 2.8 ;
    END
  END s_CNN_ly1_Out<86>
  PIN s_CNN_ly1_Out<87>
    DIRECTION INOUT ;
    USE SIGNAL ;
    PORT
      LAYER METAL3 ;
        RECT 1231.3 0.0 1232.7 2.8 ;
    END
  END s_CNN_ly1_Out<87>
  PIN s_CNN_ly1_Out<88>
    DIRECTION INOUT ;
    USE SIGNAL ;
    PORT
      LAYER METAL3 ;
        RECT 1245.3 0.0 1246.7 2.8 ;
    END
  END s_CNN_ly1_Out<88>
  PIN s_CNN_ly1_Out<89>
    DIRECTION INOUT ;
    USE SIGNAL ;
    PORT
      LAYER METAL3 ;
        RECT 1259.3 0.0 1260.7 2.8 ;
    END
  END s_CNN_ly1_Out<89>
  PIN s_CNN_ly1_Out<90>
    DIRECTION INOUT ;
    USE SIGNAL ;
    PORT
      LAYER METAL3 ;
        RECT 1273.3 0.0 1274.7 2.8 ;
    END
  END s_CNN_ly1_Out<90>
  PIN s_CNN_ly1_Out<91>
    DIRECTION INOUT ;
    USE SIGNAL ;
    PORT
      LAYER METAL3 ;
        RECT 1287.3 0.0 1288.7 2.8 ;
    END
  END s_CNN_ly1_Out<91>
  PIN s_CNN_ly1_Out<92>
    DIRECTION INOUT ;
    USE SIGNAL ;
    PORT
      LAYER METAL3 ;
        RECT 1301.3 0.0 1302.7 2.8 ;
    END
  END s_CNN_ly1_Out<92>
  PIN s_CNN_ly1_Out<93>
    DIRECTION INOUT ;
    USE SIGNAL ;
    PORT
      LAYER METAL3 ;
        RECT 1315.3 0.0 1316.7 2.8 ;
    END
  END s_CNN_ly1_Out<93>
  PIN s_CNN_ly1_Out<94>
    DIRECTION INOUT ;
    USE SIGNAL ;
    PORT
      LAYER METAL3 ;
        RECT 1329.3 0.0 1330.7 2.8 ;
    END
  END s_CNN_ly1_Out<94>
  PIN s_CNN_ly1_Out<95>
    DIRECTION INOUT ;
    USE SIGNAL ;
    PORT
      LAYER METAL3 ;
        RECT 1343.3 0.0 1344.7 2.8 ;
    END
  END s_CNN_ly1_Out<95>
  PIN s_CNN_ly1_Out<96>
    DIRECTION INOUT ;
    USE SIGNAL ;
    PORT
      LAYER METAL3 ;
        RECT 1357.3 0.0 1358.7 2.8 ;
    END
  END s_CNN_ly1_Out<96>
  PIN s_CNN_ly1_Out<97>
    DIRECTION INOUT ;
    USE SIGNAL ;
    PORT
      LAYER METAL3 ;
        RECT 1371.3 0.0 1372.7 2.8 ;
    END
  END s_CNN_ly1_Out<97>
  PIN s_CNN_ly1_Out<98>
    DIRECTION INOUT ;
    USE SIGNAL ;
    PORT
      LAYER METAL3 ;
        RECT 1385.3 0.0 1386.7 2.8 ;
    END
  END s_CNN_ly1_Out<98>
  PIN s_CNN_ly1_Out<99>
    DIRECTION INOUT ;
    USE SIGNAL ;
    PORT
      LAYER METAL3 ;
        RECT 1399.3 0.0 1400.7 2.8 ;
    END
  END s_CNN_ly1_Out<99>
  PIN s_CNN_ly1_Out<100>
    DIRECTION INOUT ;
    USE SIGNAL ;
    PORT
      LAYER METAL3 ;
        RECT 1413.3 0.0 1414.7 2.8 ;
    END
  END s_CNN_ly1_Out<100>
  PIN s_CNN_ly1_Out<101>
    DIRECTION INOUT ;
    USE SIGNAL ;
    PORT
      LAYER METAL3 ;
        RECT 1427.3 0.0 1428.7 2.8 ;
    END
  END s_CNN_ly1_Out<101>
  PIN s_CNN_ly1_Out<102>
    DIRECTION INOUT ;
    USE SIGNAL ;
    PORT
      LAYER METAL3 ;
        RECT 1441.3 0.0 1442.7 2.8 ;
    END
  END s_CNN_ly1_Out<102>
  PIN s_CNN_ly1_Out<103>
    DIRECTION INOUT ;
    USE SIGNAL ;
    PORT
      LAYER METAL3 ;
        RECT 1455.3 0.0 1456.7 2.8 ;
    END
  END s_CNN_ly1_Out<103>
  PIN s_CNN_ly1_Out<104>
    DIRECTION INOUT ;
    USE SIGNAL ;
    PORT
      LAYER METAL3 ;
        RECT 1469.3 0.0 1470.7 2.8 ;
    END
  END s_CNN_ly1_Out<104>
  PIN s_CNN_ly1_Out<105>
    DIRECTION INOUT ;
    USE SIGNAL ;
    PORT
      LAYER METAL3 ;
        RECT 1483.3 0.0 1484.7 2.8 ;
    END
  END s_CNN_ly1_Out<105>
  PIN s_CNN_ly1_Out<106>
    DIRECTION INOUT ;
    USE SIGNAL ;
    PORT
      LAYER METAL3 ;
        RECT 1497.3 0.0 1498.7 2.8 ;
    END
  END s_CNN_ly1_Out<106>
  PIN s_CNN_ly1_Out<107>
    DIRECTION INOUT ;
    USE SIGNAL ;
    PORT
      LAYER METAL3 ;
        RECT 1511.3 0.0 1512.7 2.8 ;
    END
  END s_CNN_ly1_Out<107>
  PIN s_CNN_ly1_Out<108>
    DIRECTION INOUT ;
    USE SIGNAL ;
    PORT
      LAYER METAL3 ;
        RECT 1525.3 0.0 1526.7 2.8 ;
    END
  END s_CNN_ly1_Out<108>
  PIN s_CNN_ly1_Out<109>
    DIRECTION INOUT ;
    USE SIGNAL ;
    PORT
      LAYER METAL3 ;
        RECT 1539.3 0.0 1540.7 2.8 ;
    END
  END s_CNN_ly1_Out<109>
  PIN s_CNN_ly1_Out<110>
    DIRECTION INOUT ;
    USE SIGNAL ;
    PORT
      LAYER METAL3 ;
        RECT 1553.3 0.0 1554.7 2.8 ;
    END
  END s_CNN_ly1_Out<110>
  PIN s_CNN_ly1_Out<111>
    DIRECTION INOUT ;
    USE SIGNAL ;
    PORT
      LAYER METAL3 ;
        RECT 1567.3 0.0 1568.7 2.8 ;
    END
  END s_CNN_ly1_Out<111>
  PIN s_CNN_ly1_Out<112>
    DIRECTION INOUT ;
    USE SIGNAL ;
    PORT
      LAYER METAL3 ;
        RECT 1581.3 0.0 1582.7 2.8 ;
    END
  END s_CNN_ly1_Out<112>
  PIN s_CNN_ly1_Out<113>
    DIRECTION INOUT ;
    USE SIGNAL ;
    PORT
      LAYER METAL3 ;
        RECT 1595.3 0.0 1596.7 2.8 ;
    END
  END s_CNN_ly1_Out<113>
  PIN s_CNN_ly1_Out<114>
    DIRECTION INOUT ;
    USE SIGNAL ;
    PORT
      LAYER METAL3 ;
        RECT 1609.3 0.0 1610.7 2.8 ;
    END
  END s_CNN_ly1_Out<114>
  PIN s_CNN_ly1_Out<115>
    DIRECTION INOUT ;
    USE SIGNAL ;
    PORT
      LAYER METAL3 ;
        RECT 1623.3 0.0 1624.7 2.8 ;
    END
  END s_CNN_ly1_Out<115>
  PIN s_CNN_ly1_Out<116>
    DIRECTION INOUT ;
    USE SIGNAL ;
    PORT
      LAYER METAL3 ;
        RECT 1637.3 0.0 1638.7 2.8 ;
    END
  END s_CNN_ly1_Out<116>
  PIN s_CNN_ly1_Out<117>
    DIRECTION INOUT ;
    USE SIGNAL ;
    PORT
      LAYER METAL3 ;
        RECT 1651.3 0.0 1652.7 2.8 ;
    END
  END s_CNN_ly1_Out<117>
  PIN s_CNN_ly1_Out<118>
    DIRECTION INOUT ;
    USE SIGNAL ;
    PORT
      LAYER METAL3 ;
        RECT 1665.3 0.0 1666.7 2.8 ;
    END
  END s_CNN_ly1_Out<118>
  PIN s_CNN_ly1_Out<119>
    DIRECTION INOUT ;
    USE SIGNAL ;
    PORT
      LAYER METAL3 ;
        RECT 1679.3 0.0 1680.7 2.8 ;
    END
  END s_CNN_ly1_Out<119>
  PIN s_CNN_ly1_Out<120>
    DIRECTION INOUT ;
    USE SIGNAL ;
    PORT
      LAYER METAL3 ;
        RECT 1693.3 0.0 1694.7 2.8 ;
    END
  END s_CNN_ly1_Out<120>
  PIN s_CNN_ly1_Out<121>
    DIRECTION INOUT ;
    USE SIGNAL ;
    PORT
      LAYER METAL3 ;
        RECT 1707.3 0.0 1708.7 2.8 ;
    END
  END s_CNN_ly1_Out<121>
  PIN s_CNN_ly1_Out<122>
    DIRECTION INOUT ;
    USE SIGNAL ;
    PORT
      LAYER METAL3 ;
        RECT 1721.3 0.0 1722.7 2.8 ;
    END
  END s_CNN_ly1_Out<122>
  PIN s_CNN_ly1_Out<123>
    DIRECTION INOUT ;
    USE SIGNAL ;
    PORT
      LAYER METAL3 ;
        RECT 1735.3 0.0 1736.7 2.8 ;
    END
  END s_CNN_ly1_Out<123>
  PIN s_CNN_ly1_Out<124>
    DIRECTION INOUT ;
    USE SIGNAL ;
    PORT
      LAYER METAL3 ;
        RECT 1749.3 0.0 1750.7 2.8 ;
    END
  END s_CNN_ly1_Out<124>
  PIN s_CNN_ly1_Out<125>
    DIRECTION INOUT ;
    USE SIGNAL ;
    PORT
      LAYER METAL3 ;
        RECT 1763.3 0.0 1764.7 2.8 ;
    END
  END s_CNN_ly1_Out<125>
  PIN s_CNN_ly1_Out<126>
    DIRECTION INOUT ;
    USE SIGNAL ;
    PORT
      LAYER METAL3 ;
        RECT 1777.3 0.0 1778.7 2.8 ;
    END
  END s_CNN_ly1_Out<126>
  PIN s_CNN_ly1_Out<127>
    DIRECTION INOUT ;
    USE SIGNAL ;
    PORT
      LAYER METAL3 ;
        RECT 1791.3 0.0 1792.7 2.8 ;
    END
  END s_CNN_ly1_Out<127>
  PIN s_CNN_ly1_Out<128>
    DIRECTION INOUT ;
    USE SIGNAL ;
    PORT
      LAYER METAL3 ;
        RECT 1805.3 0.0 1806.7 2.8 ;
    END
  END s_CNN_ly1_Out<128>
  PIN s_CNN_ly1_Out<129>
    DIRECTION INOUT ;
    USE SIGNAL ;
    PORT
      LAYER METAL3 ;
        RECT 1819.3 0.0 1820.7 2.8 ;
    END
  END s_CNN_ly1_Out<129>
  PIN s_CNN_ly1_Out<130>
    DIRECTION INOUT ;
    USE SIGNAL ;
    PORT
      LAYER METAL3 ;
        RECT 1833.3 0.0 1834.7 2.8 ;
    END
  END s_CNN_ly1_Out<130>
  PIN s_CNN_ly1_Out<131>
    DIRECTION INOUT ;
    USE SIGNAL ;
    PORT
      LAYER METAL3 ;
        RECT 1847.3 0.0 1848.7 2.8 ;
    END
  END s_CNN_ly1_Out<131>
  PIN s_CNN_ly1_Out<132>
    DIRECTION INOUT ;
    USE SIGNAL ;
    PORT
      LAYER METAL3 ;
        RECT 1861.3 0.0 1862.7 2.8 ;
    END
  END s_CNN_ly1_Out<132>
  PIN s_CNN_ly1_Out<133>
    DIRECTION INOUT ;
    USE SIGNAL ;
    PORT
      LAYER METAL3 ;
        RECT 1875.3 0.0 1876.7 2.8 ;
    END
  END s_CNN_ly1_Out<133>
  PIN s_CNN_ly1_Out<134>
    DIRECTION INOUT ;
    USE SIGNAL ;
    PORT
      LAYER METAL3 ;
        RECT 1889.3 0.0 1890.7 2.8 ;
    END
  END s_CNN_ly1_Out<134>
  PIN s_CNN_ly1_Out<135>
    DIRECTION INOUT ;
    USE SIGNAL ;
    PORT
      LAYER METAL3 ;
        RECT 1903.3 0.0 1904.7 2.8 ;
    END
  END s_CNN_ly1_Out<135>
  PIN s_CNN_ly1_Out<136>
    DIRECTION INOUT ;
    USE SIGNAL ;
    PORT
      LAYER METAL3 ;
        RECT 1917.3 0.0 1918.7 2.8 ;
    END
  END s_CNN_ly1_Out<136>
  PIN s_CNN_ly1_Out<137>
    DIRECTION INOUT ;
    USE SIGNAL ;
    PORT
      LAYER METAL3 ;
        RECT 1931.3 0.0 1932.7 2.8 ;
    END
  END s_CNN_ly1_Out<137>
  PIN s_CNN_ly1_Out<138>
    DIRECTION INOUT ;
    USE SIGNAL ;
    PORT
      LAYER METAL3 ;
        RECT 1945.3 0.0 1946.7 2.8 ;
    END
  END s_CNN_ly1_Out<138>
  PIN s_CNN_ly1_Out<139>
    DIRECTION INOUT ;
    USE SIGNAL ;
    PORT
      LAYER METAL3 ;
        RECT 1959.3 0.0 1960.7 2.8 ;
    END
  END s_CNN_ly1_Out<139>
  PIN s_CNN_ly1_Out<140>
    DIRECTION INOUT ;
    USE SIGNAL ;
    PORT
      LAYER METAL3 ;
        RECT 1973.3 0.0 1974.7 2.8 ;
    END
  END s_CNN_ly1_Out<140>
  PIN s_CNN_ly1_Out<141>
    DIRECTION INOUT ;
    USE SIGNAL ;
    PORT
      LAYER METAL3 ;
        RECT 1987.3 0.0 1988.7 2.8 ;
    END
  END s_CNN_ly1_Out<141>
  PIN s_CNN_ly1_Out<142>
    DIRECTION INOUT ;
    USE SIGNAL ;
    PORT
      LAYER METAL3 ;
        RECT 2001.3 0.0 2002.7 2.8 ;
    END
  END s_CNN_ly1_Out<142>
  PIN s_CNN_ly1_Out<143>
    DIRECTION INOUT ;
    USE SIGNAL ;
    PORT
      LAYER METAL3 ;
        RECT 2015.3 0.0 2016.7 2.8 ;
    END
  END s_CNN_ly1_Out<143>
  PIN s_CNN_ly1_Out<144>
    DIRECTION INOUT ;
    USE SIGNAL ;
    PORT
      LAYER METAL3 ;
        RECT 2029.3 0.0 2030.7 2.8 ;
    END
  END s_CNN_ly1_Out<144>
  PIN s_CNN_ly1_Out<145>
    DIRECTION INOUT ;
    USE SIGNAL ;
    PORT
      LAYER METAL3 ;
        RECT 2043.3 0.0 2044.7 2.8 ;
    END
  END s_CNN_ly1_Out<145>
  PIN s_CNN_ly1_Out<146>
    DIRECTION INOUT ;
    USE SIGNAL ;
    PORT
      LAYER METAL3 ;
        RECT 2057.3 0.0 2058.7 2.8 ;
    END
  END s_CNN_ly1_Out<146>
  PIN s_CNN_ly1_Out<147>
    DIRECTION INOUT ;
    USE SIGNAL ;
    PORT
      LAYER METAL3 ;
        RECT 2071.3 0.0 2072.7 2.8 ;
    END
  END s_CNN_ly1_Out<147>
  PIN s_CNN_ly1_Out<148>
    DIRECTION INOUT ;
    USE SIGNAL ;
    PORT
      LAYER METAL3 ;
        RECT 2085.3 0.0 2086.7 2.8 ;
    END
  END s_CNN_ly1_Out<148>
  PIN s_CNN_ly1_Out<149>
    DIRECTION INOUT ;
    USE SIGNAL ;
    PORT
      LAYER METAL3 ;
        RECT 2099.3 0.0 2100.7 2.8 ;
    END
  END s_CNN_ly1_Out<149>
  PIN s_CNN_ly1_Out<150>
    DIRECTION INOUT ;
    USE SIGNAL ;
    PORT
      LAYER METAL3 ;
        RECT 2113.3 0.0 2114.7 2.8 ;
    END
  END s_CNN_ly1_Out<150>
  PIN s_CNN_ly1_Out<151>
    DIRECTION INOUT ;
    USE SIGNAL ;
    PORT
      LAYER METAL3 ;
        RECT 2127.3 0.0 2128.7 2.8 ;
    END
  END s_CNN_ly1_Out<151>
  PIN s_CNN_ly1_Out<152>
    DIRECTION INOUT ;
    USE SIGNAL ;
    PORT
      LAYER METAL3 ;
        RECT 2141.3 0.0 2142.7 2.8 ;
    END
  END s_CNN_ly1_Out<152>
  PIN s_CNN_ly1_Out<153>
    DIRECTION INOUT ;
    USE SIGNAL ;
    PORT
      LAYER METAL3 ;
        RECT 2155.3 0.0 2156.7 2.8 ;
    END
  END s_CNN_ly1_Out<153>
  PIN s_CNN_ly1_Out<154>
    DIRECTION INOUT ;
    USE SIGNAL ;
    PORT
      LAYER METAL3 ;
        RECT 2169.3 0.0 2170.7 2.8 ;
    END
  END s_CNN_ly1_Out<154>
  PIN s_CNN_ly1_Out<155>
    DIRECTION INOUT ;
    USE SIGNAL ;
    PORT
      LAYER METAL3 ;
        RECT 2183.3 0.0 2184.7 2.8 ;
    END
  END s_CNN_ly1_Out<155>
  PIN s_CNN_ly1_Out<156>
    DIRECTION INOUT ;
    USE SIGNAL ;
    PORT
      LAYER METAL3 ;
        RECT 2197.3 0.0 2198.7 2.8 ;
    END
  END s_CNN_ly1_Out<156>
  PIN s_CNN_ly1_Out<157>
    DIRECTION INOUT ;
    USE SIGNAL ;
    PORT
      LAYER METAL3 ;
        RECT 2211.3 0.0 2212.7 2.8 ;
    END
  END s_CNN_ly1_Out<157>
  PIN s_CNN_ly1_Out<158>
    DIRECTION INOUT ;
    USE SIGNAL ;
    PORT
      LAYER METAL3 ;
        RECT 2225.3 0.0 2226.7 2.8 ;
    END
  END s_CNN_ly1_Out<158>
  PIN s_CNN_ly1_Out<159>
    DIRECTION INOUT ;
    USE SIGNAL ;
    PORT
      LAYER METAL3 ;
        RECT 2239.3 0.0 2240.7 2.8 ;
    END
  END s_CNN_ly1_Out<159>
  PIN s_CNN_ly1_Out<160>
    DIRECTION INOUT ;
    USE SIGNAL ;
    PORT
      LAYER METAL3 ;
        RECT 2253.3 0.0 2254.7 2.8 ;
    END
  END s_CNN_ly1_Out<160>
  PIN s_CNN_ly1_Out<161>
    DIRECTION INOUT ;
    USE SIGNAL ;
    PORT
      LAYER METAL3 ;
        RECT 2267.3 0.0 2268.7 2.8 ;
    END
  END s_CNN_ly1_Out<161>
  PIN s_CNN_ly1_Out<162>
    DIRECTION INOUT ;
    USE SIGNAL ;
    PORT
      LAYER METAL3 ;
        RECT 2281.3 0.0 2282.7 2.8 ;
    END
  END s_CNN_ly1_Out<162>
  PIN s_CNN_ly1_Out<163>
    DIRECTION INOUT ;
    USE SIGNAL ;
    PORT
      LAYER METAL3 ;
        RECT 2295.3 0.0 2296.7 2.8 ;
    END
  END s_CNN_ly1_Out<163>
  PIN s_CNN_ly1_Out<164>
    DIRECTION INOUT ;
    USE SIGNAL ;
    PORT
      LAYER METAL3 ;
        RECT 2309.3 0.0 2310.7 2.8 ;
    END
  END s_CNN_ly1_Out<164>
  PIN s_CNN_ly1_Out<165>
    DIRECTION INOUT ;
    USE SIGNAL ;
    PORT
      LAYER METAL3 ;
        RECT 2323.3 0.0 2324.7 2.8 ;
    END
  END s_CNN_ly1_Out<165>
  PIN s_CNN_ly1_Out<166>
    DIRECTION INOUT ;
    USE SIGNAL ;
    PORT
      LAYER METAL3 ;
        RECT 2337.3 0.0 2338.7 2.8 ;
    END
  END s_CNN_ly1_Out<166>
  PIN s_CNN_ly1_Out<167>
    DIRECTION INOUT ;
    USE SIGNAL ;
    PORT
      LAYER METAL3 ;
        RECT 2351.3 0.0 2352.7 2.8 ;
    END
  END s_CNN_ly1_Out<167>
  PIN s_CNN_ly1_Out<168>
    DIRECTION INOUT ;
    USE SIGNAL ;
    PORT
      LAYER METAL3 ;
        RECT 2365.3 0.0 2366.7 2.8 ;
    END
  END s_CNN_ly1_Out<168>
  PIN s_CNN_ly1_Out<169>
    DIRECTION INOUT ;
    USE SIGNAL ;
    PORT
      LAYER METAL3 ;
        RECT 2379.3 0.0 2380.7 2.8 ;
    END
  END s_CNN_ly1_Out<169>
  PIN s_CNN_ly1_Out<170>
    DIRECTION INOUT ;
    USE SIGNAL ;
    PORT
      LAYER METAL3 ;
        RECT 2393.3 0.0 2394.7 2.8 ;
    END
  END s_CNN_ly1_Out<170>
  PIN s_CNN_ly1_Out<171>
    DIRECTION INOUT ;
    USE SIGNAL ;
    PORT
      LAYER METAL3 ;
        RECT 2407.3 0.0 2408.7 2.8 ;
    END
  END s_CNN_ly1_Out<171>
  PIN s_CNN_ly1_Out<172>
    DIRECTION INOUT ;
    USE SIGNAL ;
    PORT
      LAYER METAL3 ;
        RECT 2421.3 0.0 2422.7 2.8 ;
    END
  END s_CNN_ly1_Out<172>
  PIN s_CNN_ly1_Out<173>
    DIRECTION INOUT ;
    USE SIGNAL ;
    PORT
      LAYER METAL3 ;
        RECT 2435.3 0.0 2436.7 2.8 ;
    END
  END s_CNN_ly1_Out<173>
  PIN s_CNN_ly1_Out<174>
    DIRECTION INOUT ;
    USE SIGNAL ;
    PORT
      LAYER METAL3 ;
        RECT 2449.3 0.0 2450.7 2.8 ;
    END
  END s_CNN_ly1_Out<174>
  PIN s_CNN_ly1_Out<175>
    DIRECTION INOUT ;
    USE SIGNAL ;
    PORT
      LAYER METAL3 ;
        RECT 2463.3 0.0 2464.7 2.8 ;
    END
  END s_CNN_ly1_Out<175>
  PIN s_CNN_ly1_Out<176>
    DIRECTION INOUT ;
    USE SIGNAL ;
    PORT
      LAYER METAL3 ;
        RECT 2477.3 0.0 2478.7 2.8 ;
    END
  END s_CNN_ly1_Out<176>
  PIN s_CNN_ly1_Out<177>
    DIRECTION INOUT ;
    USE SIGNAL ;
    PORT
      LAYER METAL3 ;
        RECT 2491.3 0.0 2492.7 2.8 ;
    END
  END s_CNN_ly1_Out<177>
  PIN s_CNN_ly1_Out<178>
    DIRECTION INOUT ;
    USE SIGNAL ;
    PORT
      LAYER METAL3 ;
        RECT 2505.3 0.0 2506.7 2.8 ;
    END
  END s_CNN_ly1_Out<178>
  PIN s_CNN_ly1_Out<179>
    DIRECTION INOUT ;
    USE SIGNAL ;
    PORT
      LAYER METAL3 ;
        RECT 2519.3 0.0 2520.7 2.8 ;
    END
  END s_CNN_ly1_Out<179>
  PIN s_CNN_ly1_Out<180>
    DIRECTION INOUT ;
    USE SIGNAL ;
    PORT
      LAYER METAL3 ;
        RECT 2533.3 0.0 2534.7 2.8 ;
    END
  END s_CNN_ly1_Out<180>
  PIN s_CNN_ly1_Out<181>
    DIRECTION INOUT ;
    USE SIGNAL ;
    PORT
      LAYER METAL3 ;
        RECT 2547.3 0.0 2548.7 2.8 ;
    END
  END s_CNN_ly1_Out<181>
  PIN s_CNN_ly1_Out<182>
    DIRECTION INOUT ;
    USE SIGNAL ;
    PORT
      LAYER METAL3 ;
        RECT 2561.3 0.0 2562.7 2.8 ;
    END
  END s_CNN_ly1_Out<182>
  PIN s_CNN_ly1_Out<183>
    DIRECTION INOUT ;
    USE SIGNAL ;
    PORT
      LAYER METAL3 ;
        RECT 2575.3 0.0 2576.7 2.8 ;
    END
  END s_CNN_ly1_Out<183>
END tile_analog_frame

MACRO I_Subtractor_AvgPool_core
  PIN Vd_prog_krnl
    DIRECTION INOUT ;
    USE SIGNAL ;
    PORT
      LAYER METAL2 ;
        RECT 0.0 18.88 0.37 19.88 ;
    END
  END Vd_prog_krnl
  PIN Vd_prog_avg_pool
    DIRECTION INOUT ;
    USE SIGNAL ;
    PORT
      LAYER METAL2 ;
        RECT 38.54 20.43 38.91 21.23 ;
    END
  END Vd_prog_avg_pool
  PIN Vint_out
    DIRECTION INOUT ;
    USE SIGNAL ;
    PORT
      LAYER METAL2 ;
        RECT 38.54 14.95 38.91 15.75 ;
    END
  END Vint_out
  PIN GND
    DIRECTION INOUT ;
    USE SIGNAL ;
    PORT
      LAYER METAL1 ;
        RECT 12.02 21.54 17.24 22.0 ;
    END
  END GND
  PIN Vint_in
    DIRECTION INOUT ;
    USE SIGNAL ;
    PORT
      LAYER METAL2 ;
        RECT 0.0 16.27 0.37 17.27 ;
    END
  END Vint_in
  PIN run_hv
    DIRECTION INOUT ;
    USE SIGNAL ;
    PORT
      LAYER METAL1 ;
        RECT 36.65 21.54 37.65 22.0 ;
    END
  END run_hv
  PIN VINJ
    DIRECTION INOUT ;
    USE SIGNAL ;
    PORT
      LAYER METAL1 ;
        RECT 31.8 21.54 32.8 22.0 ;
    END
  END VINJ
  PIN prog_hv
    DIRECTION INOUT ;
    USE SIGNAL ;
    PORT
      LAYER METAL1 ;
        RECT 29.8 21.54 30.8 22.0 ;
    END
  END prog_hv
END I_Subtractor_AvgPool_core

END LIBRARY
